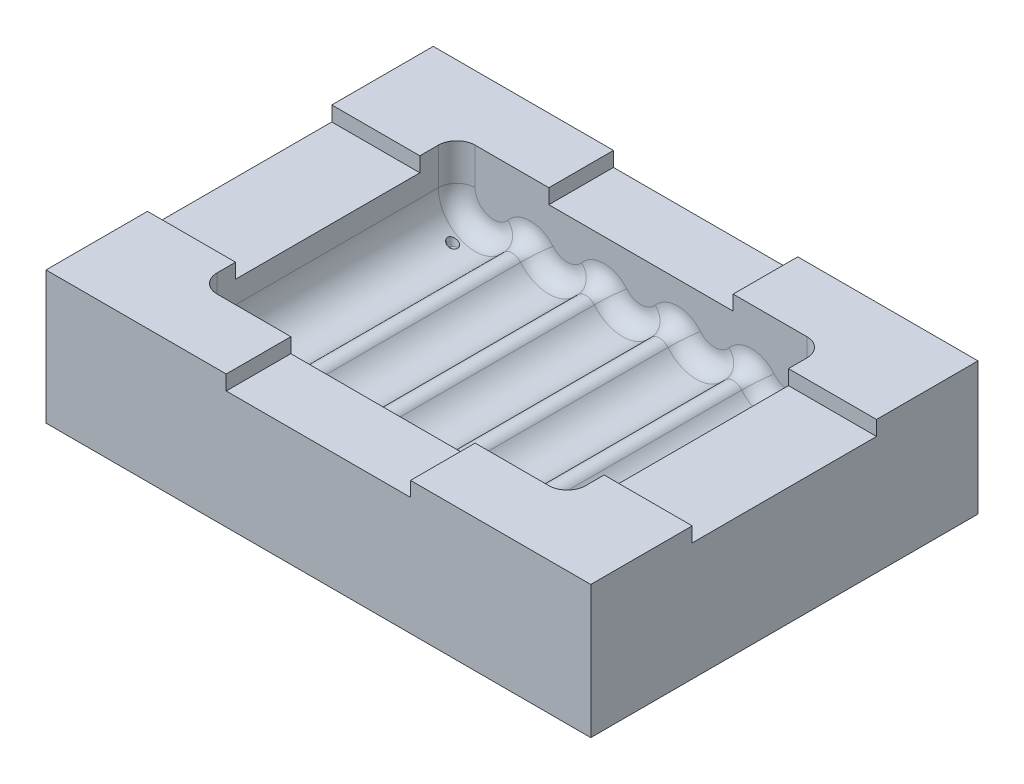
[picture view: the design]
ISO-10303-21;
HEADER;
FILE_DESCRIPTION(('STEP AP214'),'2;1');
FILE_NAME('part.step','',(''),(''),'','','');
FILE_SCHEMA(('AUTOMOTIVE_DESIGN { 1 0 10303 214 1 1 1 1 }'));
ENDSEC;
DATA;
#1=APPLICATION_CONTEXT('core data for automotive mechanical design processes');
#2=APPLICATION_PROTOCOL_DEFINITION('international standard','automotive_design',2000,#1);
#3=PRODUCT_CONTEXT('',#1,'mechanical');
#4=PRODUCT('Part','Part','',(#3));
#5=PRODUCT_RELATED_PRODUCT_CATEGORY('part','',(#4));
#6=PRODUCT_DEFINITION_FORMATION('','',#4);
#7=PRODUCT_DEFINITION_CONTEXT('part definition',#1,'design');
#8=PRODUCT_DEFINITION('design','',#6,#7);
#9=PRODUCT_DEFINITION_SHAPE('','',#8);
#10=(LENGTH_UNIT() NAMED_UNIT(*) SI_UNIT(.MILLI.,.METRE.));
#11=(NAMED_UNIT(*) PLANE_ANGLE_UNIT() SI_UNIT($,.RADIAN.));
#12=(NAMED_UNIT(*) SI_UNIT($,.STERADIAN.) SOLID_ANGLE_UNIT());
#13=UNCERTAINTY_MEASURE_WITH_UNIT(LENGTH_MEASURE(1.E-05),#10,'distance_accuracy_value','');
#14=(GEOMETRIC_REPRESENTATION_CONTEXT(3) GLOBAL_UNCERTAINTY_ASSIGNED_CONTEXT((#13)) GLOBAL_UNIT_ASSIGNED_CONTEXT((#10,
#11,#12)) REPRESENTATION_CONTEXT('',''));
#15=CARTESIAN_POINT('',(0.,0.,0.));
#16=DIRECTION('',(0.,0.,1.));
#17=DIRECTION('',(1.,0.,0.));
#18=AXIS2_PLACEMENT_3D('',#15,#16,#17);
#19=CARTESIAN_POINT('',(0.,-18.,0.));
#20=DIRECTION('',(0.,-1.,0.));
#21=DIRECTION('',(0.,0.,-1.));
#22=AXIS2_PLACEMENT_3D('',#19,#20,#21);
#23=PLANE('',#22);
#24=DIRECTION('',(0.,0.,1.));
#25=VECTOR('',#24,1.);
#26=CARTESIAN_POINT('',(-36.9482160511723,-18.,-26.2643843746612));
#27=LINE('',#26,#25);
#28=CARTESIAN_POINT('',(-36.9482160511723,-18.,-26.2643843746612));
#29=VERTEX_POINT('',#28);
#30=CARTESIAN_POINT('',(-36.9482160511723,-18.,26.2643843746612));
#31=VERTEX_POINT('',#30);
#32=EDGE_CURVE('E469',#29,#31,#27,.T.);
#33=ORIENTED_EDGE('',*,*,#32,.F.);
#34=DIRECTION('',(-1.,0.,0.));
#35=VECTOR('',#34,1.);
#36=CARTESIAN_POINT('',(36.9482160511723,-18.,-26.2643843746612));
#37=LINE('',#36,#35);
#38=CARTESIAN_POINT('',(36.9482160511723,-18.,-26.2643843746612));
#39=VERTEX_POINT('',#38);
#40=EDGE_CURVE('E484',#39,#29,#37,.T.);
#41=ORIENTED_EDGE('',*,*,#40,.F.);
#42=DIRECTION('',(0.,0.,-1.));
#43=VECTOR('',#42,1.);
#44=CARTESIAN_POINT('',(36.9482160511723,-18.,-26.2643843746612));
#45=LINE('',#44,#43);
#46=CARTESIAN_POINT('',(36.9482160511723,-18.,26.2643843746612));
#47=VERTEX_POINT('',#46);
#48=EDGE_CURVE('E471',#47,#39,#45,.T.);
#49=ORIENTED_EDGE('',*,*,#48,.F.);
#50=DIRECTION('',(1.,0.,0.));
#51=VECTOR('',#50,1.);
#52=CARTESIAN_POINT('',(36.9482160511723,-18.,26.2643843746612));
#53=LINE('',#52,#51);
#54=EDGE_CURVE('E456',#31,#47,#53,.T.);
#55=ORIENTED_EDGE('',*,*,#54,.F.);
#56=EDGE_LOOP('',(#33,#41,#49,#55));
#57=FACE_BOUND('',#56,.T.);
#58=ADVANCED_FACE('F158',(#57),#23,.T.);
#59=CARTESIAN_POINT('',(36.9482160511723,0.00150000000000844,-26.2643843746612));
#60=DIRECTION('',(0.,0.,1.));
#61=DIRECTION('',(1.,0.,0.));
#62=AXIS2_PLACEMENT_3D('',#59,#60,#61);
#63=PLANE('',#62);
#64=DIRECTION('',(0.,1.,0.));
#65=VECTOR('',#64,1.);
#66=CARTESIAN_POINT('',(12.5,0.00150000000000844,-26.2643843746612));
#67=LINE('',#66,#65);
#68=CARTESIAN_POINT('',(12.5,-2.,-26.2643843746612));
#69=VERTEX_POINT('',#68);
#70=CARTESIAN_POINT('',(12.5,0.,-26.2643843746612));
#71=VERTEX_POINT('',#70);
#72=EDGE_CURVE('E498',#69,#71,#67,.T.);
#73=ORIENTED_EDGE('',*,*,#72,.T.);
#74=DIRECTION('',(1.,0.,0.));
#75=VECTOR('',#74,1.);
#76=CARTESIAN_POINT('',(36.9482160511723,0.,-26.2643843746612));
#77=LINE('',#76,#75);
#78=CARTESIAN_POINT('',(36.9482160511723,0.,-26.2643843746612));
#79=VERTEX_POINT('',#78);
#80=EDGE_CURVE('E501',#71,#79,#77,.T.);
#81=ORIENTED_EDGE('',*,*,#80,.T.);
#82=DIRECTION('',(0.,-1.,0.));
#83=VECTOR('',#82,1.);
#84=CARTESIAN_POINT('',(36.9482160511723,0.00150000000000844,-26.2643843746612));
#85=LINE('',#84,#83);
#86=EDGE_CURVE('E487',#79,#39,#85,.T.);
#87=ORIENTED_EDGE('',*,*,#86,.T.);
#88=ORIENTED_EDGE('',*,*,#40,.T.);
#89=DIRECTION('',(0.,-1.,0.));
#90=VECTOR('',#89,1.);
#91=CARTESIAN_POINT('',(-36.9482160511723,0.00150000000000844,-26.2643843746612));
#92=LINE('',#91,#90);
#93=CARTESIAN_POINT('',(-36.9482160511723,0.,-26.2643843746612));
#94=VERTEX_POINT('',#93);
#95=EDGE_CURVE('E476',#94,#29,#92,.T.);
#96=ORIENTED_EDGE('',*,*,#95,.F.);
#97=DIRECTION('',(1.,0.,0.));
#98=VECTOR('',#97,1.);
#99=CARTESIAN_POINT('',(36.9482160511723,0.,-26.2643843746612));
#100=LINE('',#99,#98);
#101=CARTESIAN_POINT('',(-12.5,0.,-26.2643843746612));
#102=VERTEX_POINT('',#101);
#103=EDGE_CURVE('E463',#94,#102,#100,.T.);
#104=ORIENTED_EDGE('',*,*,#103,.T.);
#105=DIRECTION('',(0.,-1.,0.));
#106=VECTOR('',#105,1.);
#107=CARTESIAN_POINT('',(-12.5,0.00150000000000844,-26.2643843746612));
#108=LINE('',#107,#106);
#109=CARTESIAN_POINT('',(-12.5,-2.,-26.2643843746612));
#110=VERTEX_POINT('',#109);
#111=EDGE_CURVE('E492',#102,#110,#108,.T.);
#112=ORIENTED_EDGE('',*,*,#111,.T.);
#113=DIRECTION('',(1.,0.,0.));
#114=VECTOR('',#113,1.);
#115=CARTESIAN_POINT('',(36.9482160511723,-2.,-26.2643843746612));
#116=LINE('',#115,#114);
#117=EDGE_CURVE('E495',#110,#69,#116,.T.);
#118=ORIENTED_EDGE('',*,*,#117,.T.);
#119=EDGE_LOOP('',(#73,#81,#87,#88,#96,#104,#112,#118));
#120=FACE_BOUND('',#119,.T.);
#121=ADVANCED_FACE('F755',(#120),#63,.F.);
#122=CARTESIAN_POINT('',(36.9482160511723,0.00150000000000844,-26.2643843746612));
#123=DIRECTION('',(-1.,0.,0.));
#124=DIRECTION('',(0.,0.,1.));
#125=AXIS2_PLACEMENT_3D('',#122,#123,#124);
#126=PLANE('',#125);
#127=ORIENTED_EDGE('',*,*,#86,.F.);
#128=DIRECTION('',(0.,0.,1.));
#129=VECTOR('',#128,1.);
#130=CARTESIAN_POINT('',(36.9482160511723,0.,-26.2643843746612));
#131=LINE('',#130,#129);
#132=CARTESIAN_POINT('',(36.9482160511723,0.,-12.5));
#133=VERTEX_POINT('',#132);
#134=EDGE_CURVE('E504',#79,#133,#131,.T.);
#135=ORIENTED_EDGE('',*,*,#134,.T.);
#136=DIRECTION('',(0.,-1.,0.));
#137=VECTOR('',#136,1.);
#138=CARTESIAN_POINT('',(36.9482160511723,0.00150000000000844,-12.5));
#139=LINE('',#138,#137);
#140=CARTESIAN_POINT('',(36.9482160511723,-1.99999999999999,-12.5));
#141=VERTEX_POINT('',#140);
#142=EDGE_CURVE('E515',#133,#141,#139,.T.);
#143=ORIENTED_EDGE('',*,*,#142,.T.);
#144=DIRECTION('',(0.,0.,1.));
#145=VECTOR('',#144,1.);
#146=CARTESIAN_POINT('',(36.9482160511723,-1.99999999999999,-26.2643843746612));
#147=LINE('',#146,#145);
#148=CARTESIAN_POINT('',(36.9482160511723,-1.99999999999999,12.5));
#149=VERTEX_POINT('',#148);
#150=EDGE_CURVE('E512',#141,#149,#147,.T.);
#151=ORIENTED_EDGE('',*,*,#150,.T.);
#152=DIRECTION('',(0.,1.,0.));
#153=VECTOR('',#152,1.);
#154=CARTESIAN_POINT('',(36.9482160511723,0.00150000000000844,12.5));
#155=LINE('',#154,#153);
#156=CARTESIAN_POINT('',(36.9482160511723,0.,12.5));
#157=VERTEX_POINT('',#156);
#158=EDGE_CURVE('E509',#149,#157,#155,.T.);
#159=ORIENTED_EDGE('',*,*,#158,.T.);
#160=DIRECTION('',(0.,0.,1.));
#161=VECTOR('',#160,1.);
#162=CARTESIAN_POINT('',(36.9482160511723,0.,-26.2643843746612));
#163=LINE('',#162,#161);
#164=CARTESIAN_POINT('',(36.9482160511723,0.,26.2643843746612));
#165=VERTEX_POINT('',#164);
#166=EDGE_CURVE('E505',#157,#165,#163,.T.);
#167=ORIENTED_EDGE('',*,*,#166,.T.);
#168=DIRECTION('',(0.,-1.,0.));
#169=VECTOR('',#168,1.);
#170=CARTESIAN_POINT('',(36.9482160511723,0.00150000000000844,26.2643843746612));
#171=LINE('',#170,#169);
#172=EDGE_CURVE('E464',#165,#47,#171,.T.);
#173=ORIENTED_EDGE('',*,*,#172,.T.);
#174=ORIENTED_EDGE('',*,*,#48,.T.);
#175=EDGE_LOOP('',(#127,#135,#143,#151,#159,#167,#173,#174));
#176=FACE_BOUND('',#175,.T.);
#177=ADVANCED_FACE('F753',(#176),#126,.F.);
#178=CARTESIAN_POINT('',(36.9482160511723,0.00150000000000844,26.2643843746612));
#179=DIRECTION('',(0.,0.,-1.));
#180=DIRECTION('',(-1.,0.,0.));
#181=AXIS2_PLACEMENT_3D('',#178,#179,#180);
#182=PLANE('',#181);
#183=ORIENTED_EDGE('',*,*,#172,.F.);
#184=DIRECTION('',(-1.,0.,0.));
#185=VECTOR('',#184,1.);
#186=CARTESIAN_POINT('',(36.9482160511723,0.,26.2643843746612));
#187=LINE('',#186,#185);
#188=CARTESIAN_POINT('',(12.5,0.,26.2643843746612));
#189=VERTEX_POINT('',#188);
#190=EDGE_CURVE('E508',#165,#189,#187,.T.);
#191=ORIENTED_EDGE('',*,*,#190,.T.);
#192=DIRECTION('',(0.,-1.,0.));
#193=VECTOR('',#192,1.);
#194=CARTESIAN_POINT('',(12.5,0.00150000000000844,26.2643843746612));
#195=LINE('',#194,#193);
#196=CARTESIAN_POINT('',(12.5,-2.,26.2643843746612));
#197=VERTEX_POINT('',#196);
#198=EDGE_CURVE('E523',#189,#197,#195,.T.);
#199=ORIENTED_EDGE('',*,*,#198,.T.);
#200=DIRECTION('',(-1.,0.,0.));
#201=VECTOR('',#200,1.);
#202=CARTESIAN_POINT('',(36.9482160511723,-2.,26.2643843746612));
#203=LINE('',#202,#201);
#204=CARTESIAN_POINT('',(-12.5,-2.,26.2643843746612));
#205=VERTEX_POINT('',#204);
#206=EDGE_CURVE('E520',#197,#205,#203,.T.);
#207=ORIENTED_EDGE('',*,*,#206,.T.);
#208=DIRECTION('',(0.,1.,0.));
#209=VECTOR('',#208,1.);
#210=CARTESIAN_POINT('',(-12.5,0.00150000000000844,26.2643843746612));
#211=LINE('',#210,#209);
#212=CARTESIAN_POINT('',(-12.5,0.,26.2643843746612));
#213=VERTEX_POINT('',#212);
#214=EDGE_CURVE('E518',#205,#213,#211,.T.);
#215=ORIENTED_EDGE('',*,*,#214,.T.);
#216=DIRECTION('',(-1.,0.,0.));
#217=VECTOR('',#216,1.);
#218=CARTESIAN_POINT('',(36.9482160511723,0.,26.2643843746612));
#219=LINE('',#218,#217);
#220=CARTESIAN_POINT('',(-36.9482160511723,0.,26.2643843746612));
#221=VERTEX_POINT('',#220);
#222=EDGE_CURVE('E459',#213,#221,#219,.T.);
#223=ORIENTED_EDGE('',*,*,#222,.T.);
#224=DIRECTION('',(0.,-1.,0.));
#225=VECTOR('',#224,1.);
#226=CARTESIAN_POINT('',(-36.9482160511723,0.00150000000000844,26.2643843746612));
#227=LINE('',#226,#225);
#228=EDGE_CURVE('E452',#221,#31,#227,.T.);
#229=ORIENTED_EDGE('',*,*,#228,.T.);
#230=ORIENTED_EDGE('',*,*,#54,.T.);
#231=EDGE_LOOP('',(#183,#191,#199,#207,#215,#223,#229,#230));
#232=FACE_BOUND('',#231,.T.);
#233=ADVANCED_FACE('F455',(#232),#182,.F.);
#234=CARTESIAN_POINT('',(-36.9482160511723,0.00150000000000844,-26.2643843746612));
#235=DIRECTION('',(1.,0.,0.));
#236=DIRECTION('',(0.,0.,-1.));
#237=AXIS2_PLACEMENT_3D('',#234,#235,#236);
#238=PLANE('',#237);
#239=DIRECTION('',(0.,1.,0.));
#240=VECTOR('',#239,1.);
#241=CARTESIAN_POINT('',(-36.9482160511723,0.00150000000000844,-12.5));
#242=LINE('',#241,#240);
#243=CARTESIAN_POINT('',(-36.9482160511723,-1.99999999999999,-12.5));
#244=VERTEX_POINT('',#243);
#245=CARTESIAN_POINT('',(-36.9482160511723,0.,-12.5));
#246=VERTEX_POINT('',#245);
#247=EDGE_CURVE('E162',#244,#246,#242,.T.);
#248=ORIENTED_EDGE('',*,*,#247,.T.);
#249=DIRECTION('',(0.,0.,-1.));
#250=VECTOR('',#249,1.);
#251=CARTESIAN_POINT('',(-36.9482160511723,0.,-26.2643843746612));
#252=LINE('',#251,#250);
#253=EDGE_CURVE('E531',#246,#94,#252,.T.);
#254=ORIENTED_EDGE('',*,*,#253,.T.);
#255=ORIENTED_EDGE('',*,*,#95,.T.);
#256=ORIENTED_EDGE('',*,*,#32,.T.);
#257=ORIENTED_EDGE('',*,*,#228,.F.);
#258=DIRECTION('',(0.,0.,-1.));
#259=VECTOR('',#258,1.);
#260=CARTESIAN_POINT('',(-36.9482160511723,0.,-26.2643843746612));
#261=LINE('',#260,#259);
#262=CARTESIAN_POINT('',(-36.9482160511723,0.,12.5));
#263=VERTEX_POINT('',#262);
#264=EDGE_CURVE('E480',#221,#263,#261,.T.);
#265=ORIENTED_EDGE('',*,*,#264,.T.);
#266=DIRECTION('',(0.,-1.,0.));
#267=VECTOR('',#266,1.);
#268=CARTESIAN_POINT('',(-36.9482160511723,0.00150000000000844,12.5));
#269=LINE('',#268,#267);
#270=CARTESIAN_POINT('',(-36.9482160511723,-1.99999999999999,12.5));
#271=VERTEX_POINT('',#270);
#272=EDGE_CURVE('E527',#263,#271,#269,.T.);
#273=ORIENTED_EDGE('',*,*,#272,.T.);
#274=DIRECTION('',(0.,0.,-1.));
#275=VECTOR('',#274,1.);
#276=CARTESIAN_POINT('',(-36.9482160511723,-1.99999999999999,-26.2643843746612));
#277=LINE('',#276,#275);
#278=EDGE_CURVE('E529',#271,#244,#277,.T.);
#279=ORIENTED_EDGE('',*,*,#278,.T.);
#280=EDGE_LOOP('',(#248,#254,#255,#256,#257,#265,#273,#279));
#281=FACE_BOUND('',#280,.T.);
#282=ADVANCED_FACE('F160',(#281),#238,.F.);
#283=CARTESIAN_POINT('',(-25.,-1.99999999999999,-12.5));
#284=DIRECTION('',(0.,0.,-1.));
#285=DIRECTION('',(-1.,0.,0.));
#286=AXIS2_PLACEMENT_3D('',#283,#284,#285);
#287=PLANE('',#286);
#288=CARTESIAN_POINT('',(-25.,-1.99999999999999,-12.5));
#289=CARTESIAN_POINT('',(-45.,-1.99999999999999,-12.5));
#290=B_SPLINE_CURVE_WITH_KNOTS('',1,(#288,#289),.UNSPECIFIED.,.F.,.F.,(2,2),(0.,1.),.UNSPECIFIED.);
#291=CARTESIAN_POINT('',(-25.,-1.99999999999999,-12.5));
#292=VERTEX_POINT('',#291);
#293=EDGE_CURVE('E532',#292,#244,#290,.T.);
#294=ORIENTED_EDGE('',*,*,#293,.F.);
#295=DIRECTION('',(0.,1.,0.));
#296=VECTOR('',#295,1.);
#297=CARTESIAN_POINT('',(-25.,2.00000000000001,-12.5));
#298=LINE('',#297,#296);
#299=CARTESIAN_POINT('',(-25.,0.,-12.5));
#300=VERTEX_POINT('',#299);
#301=EDGE_CURVE('E559',#292,#300,#298,.T.);
#302=ORIENTED_EDGE('',*,*,#301,.T.);
#303=DIRECTION('',(-1.,0.,0.));
#304=VECTOR('',#303,1.);
#305=CARTESIAN_POINT('',(-25.,0.,-12.5));
#306=LINE('',#305,#304);
#307=EDGE_CURVE('E535',#300,#246,#306,.T.);
#308=ORIENTED_EDGE('',*,*,#307,.T.);
#309=ORIENTED_EDGE('',*,*,#247,.F.);
#310=EDGE_LOOP('',(#294,#302,#308,#309));
#311=FACE_BOUND('',#310,.T.);
#312=ADVANCED_FACE('F894',(#311),#287,.F.);
#313=CARTESIAN_POINT('',(-25.,-1.99999999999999,12.5));
#314=DIRECTION('',(0.,-1.,0.));
#315=DIRECTION('',(0.,0.,-1.));
#316=AXIS2_PLACEMENT_3D('',#313,#314,#315);
#317=PLANE('',#316);
#318=DIRECTION('',(-1.,0.,0.));
#319=VECTOR('',#318,1.);
#320=CARTESIAN_POINT('',(-25.,-1.99999999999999,12.5));
#321=LINE('',#320,#319);
#322=CARTESIAN_POINT('',(-25.,-1.99999999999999,12.5));
#323=VERTEX_POINT('',#322);
#324=EDGE_CURVE('E584',#323,#271,#321,.T.);
#325=ORIENTED_EDGE('',*,*,#324,.F.);
#326=DIRECTION('',(0.,0.,-1.));
#327=VECTOR('',#326,1.);
#328=CARTESIAN_POINT('',(-25.,-1.99999999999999,12.5));
#329=LINE('',#328,#327);
#330=EDGE_CURVE('E843',#323,#292,#329,.T.);
#331=ORIENTED_EDGE('',*,*,#330,.T.);
#332=ORIENTED_EDGE('',*,*,#293,.T.);
#333=ORIENTED_EDGE('',*,*,#278,.F.);
#334=EDGE_LOOP('',(#325,#331,#332,#333));
#335=FACE_BOUND('',#334,.T.);
#336=ADVANCED_FACE('F885',(#335),#317,.F.);
#337=CARTESIAN_POINT('',(-25.,0.,12.5));
#338=DIRECTION('',(0.,0.,1.));
#339=DIRECTION('',(-1.,0.,0.));
#340=AXIS2_PLACEMENT_3D('',#337,#338,#339);
#341=PLANE('',#340);
#342=CARTESIAN_POINT('',(-25.,0.,12.5));
#343=CARTESIAN_POINT('',(-45.,0.,12.5));
#344=B_SPLINE_CURVE_WITH_KNOTS('',1,(#342,#343),.UNSPECIFIED.,.F.,.F.,(2,2),(0.,1.),.UNSPECIFIED.);
#345=CARTESIAN_POINT('',(-25.,0.,12.5));
#346=VERTEX_POINT('',#345);
#347=EDGE_CURVE('E841',#346,#263,#344,.T.);
#348=ORIENTED_EDGE('',*,*,#347,.F.);
#349=DIRECTION('',(0.,-1.,0.));
#350=VECTOR('',#349,1.);
#351=CARTESIAN_POINT('',(-25.,2.00000000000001,12.5));
#352=LINE('',#351,#350);
#353=EDGE_CURVE('E655',#346,#323,#352,.T.);
#354=ORIENTED_EDGE('',*,*,#353,.T.);
#355=ORIENTED_EDGE('',*,*,#324,.T.);
#356=ORIENTED_EDGE('',*,*,#272,.F.);
#357=EDGE_LOOP('',(#348,#354,#355,#356));
#358=FACE_BOUND('',#357,.T.);
#359=ADVANCED_FACE('F876',(#358),#341,.F.);
#360=CARTESIAN_POINT('',(12.5,0.,17.5));
#361=DIRECTION('',(1.,0.,0.));
#362=DIRECTION('',(0.,0.,1.));
#363=AXIS2_PLACEMENT_3D('',#360,#361,#362);
#364=PLANE('',#363);
#365=DIRECTION('',(0.,0.,1.));
#366=VECTOR('',#365,1.);
#367=CARTESIAN_POINT('',(12.5,0.,17.5));
#368=LINE('',#367,#366);
#369=CARTESIAN_POINT('',(12.5,0.,17.5));
#370=VERTEX_POINT('',#369);
#371=EDGE_CURVE('E596',#370,#189,#368,.T.);
#372=ORIENTED_EDGE('',*,*,#371,.F.);
#373=DIRECTION('',(0.,1.,0.));
#374=VECTOR('',#373,1.);
#375=CARTESIAN_POINT('',(12.5,2.,17.5));
#376=LINE('',#375,#374);
#377=CARTESIAN_POINT('',(12.5,-2.,17.5));
#378=VERTEX_POINT('',#377);
#379=EDGE_CURVE('E595',#378,#370,#376,.T.);
#380=ORIENTED_EDGE('',*,*,#379,.F.);
#381=CARTESIAN_POINT('',(12.5,-2.,17.5));
#382=CARTESIAN_POINT('',(12.5,-2.,37.5));
#383=B_SPLINE_CURVE_WITH_KNOTS('',1,(#381,#382),.UNSPECIFIED.,.F.,.F.,(2,2),(0.,1.),.UNSPECIFIED.);
#384=EDGE_CURVE('E593',#197,#378,#383,.F.);
#385=ORIENTED_EDGE('',*,*,#384,.F.);
#386=ORIENTED_EDGE('',*,*,#198,.F.);
#387=EDGE_LOOP('',(#372,#380,#385,#386));
#388=FACE_BOUND('',#387,.T.);
#389=ADVANCED_FACE('F861',(#388),#364,.F.);
#390=CARTESIAN_POINT('',(-12.5,0.,17.5));
#391=DIRECTION('',(0.,-1.,0.));
#392=DIRECTION('',(0.,0.,-1.));
#393=AXIS2_PLACEMENT_3D('',#390,#391,#392);
#394=PLANE('',#393);
#395=ORIENTED_EDGE('',*,*,#222,.F.);
#396=DIRECTION('',(0.,0.,1.));
#397=VECTOR('',#396,1.);
#398=CARTESIAN_POINT('',(-12.5,0.,17.5));
#399=LINE('',#398,#397);
#400=CARTESIAN_POINT('',(-12.5,0.,17.5));
#401=VERTEX_POINT('',#400);
#402=EDGE_CURVE('E624',#401,#213,#399,.T.);
#403=ORIENTED_EDGE('',*,*,#402,.F.);
#404=DIRECTION('',(-1.,0.,0.));
#405=VECTOR('',#404,1.);
#406=CARTESIAN_POINT('',(-25.,0.,17.5));
#407=LINE('',#406,#405);
#408=CARTESIAN_POINT('',(-22.5,0.,17.5));
#409=VERTEX_POINT('',#408);
#410=EDGE_CURVE('E621',#401,#409,#407,.T.);
#411=ORIENTED_EDGE('',*,*,#410,.T.);
#412=CARTESIAN_POINT('',(-22.5,0.,15.));
#413=DIRECTION('',(0.,-1.,0.));
#414=DIRECTION('',(1.,0.,0.));
#415=AXIS2_PLACEMENT_3D('',#412,#413,#414);
#416=CIRCLE('',#415,2.5);
#417=CARTESIAN_POINT('',(-25.,0.,15.));
#418=VERTEX_POINT('',#417);
#419=EDGE_CURVE('E625',#418,#409,#416,.F.);
#420=ORIENTED_EDGE('',*,*,#419,.F.);
#421=DIRECTION('',(0.,0.,-1.));
#422=VECTOR('',#421,1.);
#423=CARTESIAN_POINT('',(-25.,0.,17.5));
#424=LINE('',#423,#422);
#425=EDGE_CURVE('E640',#418,#346,#424,.T.);
#426=ORIENTED_EDGE('',*,*,#425,.T.);
#427=ORIENTED_EDGE('',*,*,#347,.T.);
#428=ORIENTED_EDGE('',*,*,#264,.F.);
#429=EDGE_LOOP('',(#395,#403,#411,#420,#426,#427,#428));
#430=FACE_BOUND('',#429,.T.);
#431=ADVANCED_FACE('F982',(#430),#394,.F.);
#432=CARTESIAN_POINT('',(12.5,-2.,17.5));
#433=DIRECTION('',(0.,-1.,0.));
#434=DIRECTION('',(0.,0.,-1.));
#435=AXIS2_PLACEMENT_3D('',#432,#433,#434);
#436=PLANE('',#435);
#437=ORIENTED_EDGE('',*,*,#384,.T.);
#438=DIRECTION('',(1.,0.,0.));
#439=VECTOR('',#438,1.);
#440=CARTESIAN_POINT('',(-12.5,-2.,17.5));
#441=LINE('',#440,#439);
#442=CARTESIAN_POINT('',(-12.5,-2.,17.5));
#443=VERTEX_POINT('',#442);
#444=EDGE_CURVE('E633',#443,#378,#441,.T.);
#445=ORIENTED_EDGE('',*,*,#444,.F.);
#446=DIRECTION('',(0.,0.,1.));
#447=VECTOR('',#446,1.);
#448=CARTESIAN_POINT('',(-12.5,-2.,17.5));
#449=LINE('',#448,#447);
#450=EDGE_CURVE('E638',#443,#205,#449,.T.);
#451=ORIENTED_EDGE('',*,*,#450,.T.);
#452=ORIENTED_EDGE('',*,*,#206,.F.);
#453=EDGE_LOOP('',(#437,#445,#451,#452));
#454=FACE_BOUND('',#453,.T.);
#455=ADVANCED_FACE('F854',(#454),#436,.F.);
#456=CARTESIAN_POINT('',(-12.5,-2.,17.5));
#457=DIRECTION('',(-1.,0.,0.));
#458=DIRECTION('',(0.,0.,1.));
#459=AXIS2_PLACEMENT_3D('',#456,#457,#458);
#460=PLANE('',#459);
#461=ORIENTED_EDGE('',*,*,#450,.F.);
#462=DIRECTION('',(0.,-1.,0.));
#463=VECTOR('',#462,1.);
#464=CARTESIAN_POINT('',(-12.5,2.,17.5));
#465=LINE('',#464,#463);
#466=EDGE_CURVE('E631',#401,#443,#465,.T.);
#467=ORIENTED_EDGE('',*,*,#466,.F.);
#468=ORIENTED_EDGE('',*,*,#402,.T.);
#469=ORIENTED_EDGE('',*,*,#214,.F.);
#470=EDGE_LOOP('',(#461,#467,#468,#469));
#471=FACE_BOUND('',#470,.T.);
#472=ADVANCED_FACE('F987',(#471),#460,.F.);
#473=CARTESIAN_POINT('',(25.,0.,-12.5));
#474=DIRECTION('',(0.,0.,-1.));
#475=DIRECTION('',(1.,0.,0.));
#476=AXIS2_PLACEMENT_3D('',#473,#474,#475);
#477=PLANE('',#476);
#478=DIRECTION('',(1.,0.,0.));
#479=VECTOR('',#478,1.);
#480=CARTESIAN_POINT('',(25.,0.,-12.5));
#481=LINE('',#480,#479);
#482=CARTESIAN_POINT('',(25.,0.,-12.5));
#483=VERTEX_POINT('',#482);
#484=EDGE_CURVE('E592',#483,#133,#481,.T.);
#485=ORIENTED_EDGE('',*,*,#484,.F.);
#486=DIRECTION('',(0.,1.,0.));
#487=VECTOR('',#486,1.);
#488=CARTESIAN_POINT('',(25.,2.00000000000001,-12.5));
#489=LINE('',#488,#487);
#490=CARTESIAN_POINT('',(25.,-1.99999999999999,-12.5));
#491=VERTEX_POINT('',#490);
#492=EDGE_CURVE('E577',#491,#483,#489,.T.);
#493=ORIENTED_EDGE('',*,*,#492,.F.);
#494=CARTESIAN_POINT('',(25.,-1.99999999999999,-12.5));
#495=CARTESIAN_POINT('',(45.,-1.99999999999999,-12.5));
#496=B_SPLINE_CURVE_WITH_KNOTS('',1,(#494,#495),.UNSPECIFIED.,.F.,.F.,(2,2),(0.,1.),.UNSPECIFIED.);
#497=EDGE_CURVE('E590',#141,#491,#496,.F.);
#498=ORIENTED_EDGE('',*,*,#497,.F.);
#499=ORIENTED_EDGE('',*,*,#142,.F.);
#500=EDGE_LOOP('',(#485,#493,#498,#499));
#501=FACE_BOUND('',#500,.T.);
#502=ADVANCED_FACE('F816',(#501),#477,.F.);
#503=CARTESIAN_POINT('',(25.,-1.99999999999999,-12.5));
#504=DIRECTION('',(0.,-1.,0.));
#505=DIRECTION('',(0.,0.,-1.));
#506=AXIS2_PLACEMENT_3D('',#503,#504,#505);
#507=PLANE('',#506);
#508=ORIENTED_EDGE('',*,*,#497,.T.);
#509=DIRECTION('',(0.,0.,-1.));
#510=VECTOR('',#509,1.);
#511=CARTESIAN_POINT('',(25.,-1.99999999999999,12.5));
#512=LINE('',#511,#510);
#513=CARTESIAN_POINT('',(25.,-1.99999999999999,12.5));
#514=VERTEX_POINT('',#513);
#515=EDGE_CURVE('E576',#514,#491,#512,.T.);
#516=ORIENTED_EDGE('',*,*,#515,.F.);
#517=DIRECTION('',(1.,0.,0.));
#518=VECTOR('',#517,1.);
#519=CARTESIAN_POINT('',(25.,-1.99999999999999,12.5));
#520=LINE('',#519,#518);
#521=EDGE_CURVE('E570',#514,#149,#520,.T.);
#522=ORIENTED_EDGE('',*,*,#521,.T.);
#523=ORIENTED_EDGE('',*,*,#150,.F.);
#524=EDGE_LOOP('',(#508,#516,#522,#523));
#525=FACE_BOUND('',#524,.T.);
#526=ADVANCED_FACE('F818',(#525),#507,.F.);
#527=CARTESIAN_POINT('',(25.,-1.99999999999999,12.5));
#528=DIRECTION('',(0.,0.,1.));
#529=DIRECTION('',(1.,0.,0.));
#530=AXIS2_PLACEMENT_3D('',#527,#528,#529);
#531=PLANE('',#530);
#532=ORIENTED_EDGE('',*,*,#521,.F.);
#533=DIRECTION('',(0.,-1.,0.));
#534=VECTOR('',#533,1.);
#535=CARTESIAN_POINT('',(25.,2.00000000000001,12.5));
#536=LINE('',#535,#534);
#537=CARTESIAN_POINT('',(25.,0.,12.5));
#538=VERTEX_POINT('',#537);
#539=EDGE_CURVE('E612',#538,#514,#536,.T.);
#540=ORIENTED_EDGE('',*,*,#539,.F.);
#541=CARTESIAN_POINT('',(25.,0.,12.5));
#542=CARTESIAN_POINT('',(45.,0.,12.5));
#543=B_SPLINE_CURVE_WITH_KNOTS('',1,(#541,#542),.UNSPECIFIED.,.F.,.F.,(2,2),(0.,1.),.UNSPECIFIED.);
#544=EDGE_CURVE('E807',#157,#538,#543,.F.);
#545=ORIENTED_EDGE('',*,*,#544,.F.);
#546=ORIENTED_EDGE('',*,*,#158,.F.);
#547=EDGE_LOOP('',(#532,#540,#545,#546));
#548=FACE_BOUND('',#547,.T.);
#549=ADVANCED_FACE('F822',(#548),#531,.F.);
#550=CARTESIAN_POINT('',(25.,0.,12.5));
#551=DIRECTION('',(0.,-1.,0.));
#552=DIRECTION('',(0.,0.,-1.));
#553=AXIS2_PLACEMENT_3D('',#550,#551,#552);
#554=PLANE('',#553);
#555=ORIENTED_EDGE('',*,*,#166,.F.);
#556=ORIENTED_EDGE('',*,*,#544,.T.);
#557=DIRECTION('',(0.,0.,-1.));
#558=VECTOR('',#557,1.);
#559=CARTESIAN_POINT('',(25.,0.,17.5));
#560=LINE('',#559,#558);
#561=CARTESIAN_POINT('',(25.,0.,15.));
#562=VERTEX_POINT('',#561);
#563=EDGE_CURVE('E735',#562,#538,#560,.T.);
#564=ORIENTED_EDGE('',*,*,#563,.F.);
#565=CARTESIAN_POINT('',(22.5,0.,15.));
#566=DIRECTION('',(0.,-1.,0.));
#567=DIRECTION('',(1.,0.,0.));
#568=AXIS2_PLACEMENT_3D('',#565,#566,#567);
#569=CIRCLE('',#568,2.5);
#570=CARTESIAN_POINT('',(22.5,0.,17.5));
#571=VERTEX_POINT('',#570);
#572=EDGE_CURVE('E611',#571,#562,#569,.F.);
#573=ORIENTED_EDGE('',*,*,#572,.F.);
#574=EDGE_CURVE('E604',#571,#370,#407,.T.);
#575=ORIENTED_EDGE('',*,*,#574,.T.);
#576=ORIENTED_EDGE('',*,*,#371,.T.);
#577=ORIENTED_EDGE('',*,*,#190,.F.);
#578=EDGE_LOOP('',(#555,#556,#564,#573,#575,#576,#577));
#579=FACE_BOUND('',#578,.T.);
#580=ADVANCED_FACE('F862',(#579),#554,.F.);
#581=CARTESIAN_POINT('',(12.5,-2.,-17.5));
#582=DIRECTION('',(1.,0.,0.));
#583=DIRECTION('',(0.,0.,-1.));
#584=AXIS2_PLACEMENT_3D('',#581,#582,#583);
#585=PLANE('',#584);
#586=CARTESIAN_POINT('',(12.5,-2.,-17.5));
#587=CARTESIAN_POINT('',(12.5,-2.,-37.5));
#588=B_SPLINE_CURVE_WITH_KNOTS('',1,(#586,#587),.UNSPECIFIED.,.F.,.F.,(2,2),(0.,1.),.UNSPECIFIED.);
#589=CARTESIAN_POINT('',(12.5,-2.,-17.5));
#590=VERTEX_POINT('',#589);
#591=EDGE_CURVE('E545',#590,#69,#588,.T.);
#592=ORIENTED_EDGE('',*,*,#591,.F.);
#593=DIRECTION('',(0.,1.,0.));
#594=VECTOR('',#593,1.);
#595=CARTESIAN_POINT('',(12.5,2.,-17.5));
#596=LINE('',#595,#594);
#597=CARTESIAN_POINT('',(12.5,0.,-17.5));
#598=VERTEX_POINT('',#597);
#599=EDGE_CURVE('E544',#590,#598,#596,.T.);
#600=ORIENTED_EDGE('',*,*,#599,.T.);
#601=CARTESIAN_POINT('',(12.5,0.,-17.5));
#602=CARTESIAN_POINT('',(12.5,0.,-37.5));
#603=B_SPLINE_CURVE_WITH_KNOTS('',1,(#601,#602),.UNSPECIFIED.,.F.,.F.,(2,2),(0.,1.),.UNSPECIFIED.);
#604=EDGE_CURVE('E541',#71,#598,#603,.F.);
#605=ORIENTED_EDGE('',*,*,#604,.F.);
#606=ORIENTED_EDGE('',*,*,#72,.F.);
#607=EDGE_LOOP('',(#592,#600,#605,#606));
#608=FACE_BOUND('',#607,.T.);
#609=ADVANCED_FACE('F757',(#608),#585,.F.);
#610=CARTESIAN_POINT('',(-12.5,-2.,-17.5));
#611=DIRECTION('',(0.,-1.,0.));
#612=DIRECTION('',(0.,0.,-1.));
#613=AXIS2_PLACEMENT_3D('',#610,#611,#612);
#614=PLANE('',#613);
#615=DIRECTION('',(0.,0.,-1.));
#616=VECTOR('',#615,1.);
#617=CARTESIAN_POINT('',(-12.5,-2.,-17.5));
#618=LINE('',#617,#616);
#619=CARTESIAN_POINT('',(-12.5,-2.,-17.5));
#620=VERTEX_POINT('',#619);
#621=EDGE_CURVE('E717',#620,#110,#618,.T.);
#622=ORIENTED_EDGE('',*,*,#621,.F.);
#623=DIRECTION('',(1.,0.,0.));
#624=VECTOR('',#623,1.);
#625=CARTESIAN_POINT('',(-12.5,-2.,-17.5));
#626=LINE('',#625,#624);
#627=EDGE_CURVE('E713',#620,#590,#626,.T.);
#628=ORIENTED_EDGE('',*,*,#627,.T.);
#629=ORIENTED_EDGE('',*,*,#591,.T.);
#630=ORIENTED_EDGE('',*,*,#117,.F.);
#631=EDGE_LOOP('',(#622,#628,#629,#630));
#632=FACE_BOUND('',#631,.T.);
#633=ADVANCED_FACE('F759',(#632),#614,.F.);
#634=CARTESIAN_POINT('',(12.5,0.,-17.5));
#635=DIRECTION('',(0.,-1.,0.));
#636=DIRECTION('',(0.,0.,-1.));
#637=AXIS2_PLACEMENT_3D('',#634,#635,#636);
#638=PLANE('',#637);
#639=ORIENTED_EDGE('',*,*,#80,.F.);
#640=ORIENTED_EDGE('',*,*,#604,.T.);
#641=DIRECTION('',(-1.,0.,0.));
#642=VECTOR('',#641,1.);
#643=CARTESIAN_POINT('',(-25.,0.,-17.5));
#644=LINE('',#643,#642);
#645=CARTESIAN_POINT('',(22.5,0.,-17.5));
#646=VERTEX_POINT('',#645);
#647=EDGE_CURVE('E565',#646,#598,#644,.T.);
#648=ORIENTED_EDGE('',*,*,#647,.F.);
#649=CARTESIAN_POINT('',(22.5,0.,-15.));
#650=DIRECTION('',(0.,-1.,0.));
#651=DIRECTION('',(1.,0.,0.));
#652=AXIS2_PLACEMENT_3D('',#649,#650,#651);
#653=CIRCLE('',#652,2.5);
#654=CARTESIAN_POINT('',(25.,0.,-15.));
#655=VERTEX_POINT('',#654);
#656=EDGE_CURVE('E703',#655,#646,#653,.F.);
#657=ORIENTED_EDGE('',*,*,#656,.F.);
#658=EDGE_CURVE('E716',#483,#655,#560,.T.);
#659=ORIENTED_EDGE('',*,*,#658,.F.);
#660=ORIENTED_EDGE('',*,*,#484,.T.);
#661=ORIENTED_EDGE('',*,*,#134,.F.);
#662=EDGE_LOOP('',(#639,#640,#648,#657,#659,#660,#661));
#663=FACE_BOUND('',#662,.T.);
#664=ADVANCED_FACE('F747',(#663),#638,.F.);
#665=CARTESIAN_POINT('',(-12.5,0.,-17.5));
#666=DIRECTION('',(-1.,0.,0.));
#667=DIRECTION('',(0.,0.,-1.));
#668=AXIS2_PLACEMENT_3D('',#665,#666,#667);
#669=PLANE('',#668);
#670=CARTESIAN_POINT('',(-12.5,0.,-17.5));
#671=CARTESIAN_POINT('',(-12.5,0.,-37.5));
#672=B_SPLINE_CURVE_WITH_KNOTS('',1,(#670,#671),.UNSPECIFIED.,.F.,.F.,(2,2),(0.,1.),.UNSPECIFIED.);
#673=CARTESIAN_POINT('',(-12.5,0.,-17.5));
#674=VERTEX_POINT('',#673);
#675=EDGE_CURVE('E562',#674,#102,#672,.T.);
#676=ORIENTED_EDGE('',*,*,#675,.F.);
#677=DIRECTION('',(0.,-1.,0.));
#678=VECTOR('',#677,1.);
#679=CARTESIAN_POINT('',(-12.5,2.,-17.5));
#680=LINE('',#679,#678);
#681=EDGE_CURVE('E564',#674,#620,#680,.T.);
#682=ORIENTED_EDGE('',*,*,#681,.T.);
#683=ORIENTED_EDGE('',*,*,#621,.T.);
#684=ORIENTED_EDGE('',*,*,#111,.F.);
#685=EDGE_LOOP('',(#676,#682,#683,#684));
#686=FACE_BOUND('',#685,.T.);
#687=ADVANCED_FACE('F761',(#686),#669,.F.);
#688=CARTESIAN_POINT('',(-25.,0.,-12.5));
#689=DIRECTION('',(0.,-1.,0.));
#690=DIRECTION('',(0.,0.,-1.));
#691=AXIS2_PLACEMENT_3D('',#688,#689,#690);
#692=PLANE('',#691);
#693=ORIENTED_EDGE('',*,*,#307,.F.);
#694=CARTESIAN_POINT('',(-25.,0.,-15.));
#695=VERTEX_POINT('',#694);
#696=EDGE_CURVE('E666',#300,#695,#424,.T.);
#697=ORIENTED_EDGE('',*,*,#696,.T.);
#698=CARTESIAN_POINT('',(-22.5,0.,-15.));
#699=DIRECTION('',(0.,-1.,0.));
#700=DIRECTION('',(1.,0.,0.));
#701=AXIS2_PLACEMENT_3D('',#698,#699,#700);
#702=CIRCLE('',#701,2.5);
#703=CARTESIAN_POINT('',(-22.5,0.,-17.5));
#704=VERTEX_POINT('',#703);
#705=EDGE_CURVE('E670',#704,#695,#702,.F.);
#706=ORIENTED_EDGE('',*,*,#705,.F.);
#707=EDGE_CURVE('E689',#674,#704,#644,.T.);
#708=ORIENTED_EDGE('',*,*,#707,.F.);
#709=ORIENTED_EDGE('',*,*,#675,.T.);
#710=ORIENTED_EDGE('',*,*,#103,.F.);
#711=ORIENTED_EDGE('',*,*,#253,.F.);
#712=EDGE_LOOP('',(#693,#697,#706,#708,#709,#710,#711));
#713=FACE_BOUND('',#712,.T.);
#714=ADVANCED_FACE('F766',(#713),#692,.F.);
#715=CARTESIAN_POINT('',(-22.,-10.5,-14.));
#716=DIRECTION('',(0.,1.,0.));
#717=DIRECTION('',(0.,0.,1.));
#718=AXIS2_PLACEMENT_3D('',#715,#716,#717);
#719=PLANE('',#718);
#720=CARTESIAN_POINT('',(-22.,-10.5,-14.));
#721=DIRECTION('',(0.,1.,0.));
#722=DIRECTION('',(0.,0.,1.));
#723=AXIS2_PLACEMENT_3D('',#720,#721,#722);
#724=CIRCLE('',#723,0.290225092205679);
#725=CARTESIAN_POINT('',(-22.,-10.5,-13.7097749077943));
#726=VERTEX_POINT('',#725);
#727=EDGE_CURVE('E669',#726,#726,#724,.F.);
#728=ORIENTED_EDGE('',*,*,#727,.F.);
#729=EDGE_LOOP('',(#728));
#730=FACE_BOUND('',#729,.T.);
#731=ADVANCED_FACE('F965',(#730),#719,.T.);
#732=CARTESIAN_POINT('',(-22.,-10.25,-14.));
#733=DIRECTION('',(0.,1.,0.));
#734=DIRECTION('',(0.,0.,1.));
#735=AXIS2_PLACEMENT_3D('',#732,#733,#734);
#736=TOROIDAL_SURFACE('',#735,0.290225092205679,0.25);
#737=ORIENTED_EDGE('',*,*,#727,.T.);
#738=EDGE_LOOP('',(#737));
#739=FACE_BOUND('',#738,.T.);
#740=CARTESIAN_POINT('',(-22.,-10.2934120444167,-14.));
#741=DIRECTION('',(0.,-1.,0.));
#742=DIRECTION('',(0.,0.,-1.));
#743=AXIS2_PLACEMENT_3D('',#740,#741,#742);
#744=CIRCLE('',#743,0.536427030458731);
#745=CARTESIAN_POINT('',(-22.,-10.2934120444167,-14.5364270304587));
#746=VERTEX_POINT('',#745);
#747=EDGE_CURVE('E1661',#746,#746,#744,.F.);
#748=ORIENTED_EDGE('',*,*,#747,.T.);
#749=EDGE_LOOP('',(#748));
#750=FACE_BOUND('',#749,.T.);
#751=ADVANCED_FACE('F961',(#739,#750),#736,.F.);
#752=CARTESIAN_POINT('',(-22.,-10.5,-14.));
#753=DIRECTION('',(0.,1.,0.));
#754=DIRECTION('',(0.,0.,1.));
#755=AXIS2_PLACEMENT_3D('',#752,#753,#754);
#756=CONICAL_SURFACE('',#755,0.499999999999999,0.174532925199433);
#757=ORIENTED_EDGE('',*,*,#747,.F.);
#758=EDGE_LOOP('',(#757));
#759=FACE_BOUND('',#758,.T.);
#760=CARTESIAN_POINT('',(-22.522981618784,-9.31677700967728,-14.4781762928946));
#761=CARTESIAN_POINT('',(-22.4885081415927,-9.33692418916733,-14.5106134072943));
#762=CARTESIAN_POINT('',(-22.4509534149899,-9.35831249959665,-14.539102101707));
#763=CARTESIAN_POINT('',(-22.3712514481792,-9.40218636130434,-14.5876995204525));
#764=CARTESIAN_POINT('',(-22.3290921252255,-9.42467470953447,-14.6077854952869));
#765=CARTESIAN_POINT('',(-22.2462877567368,-9.46722756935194,-14.6374307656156));
#766=CARTESIAN_POINT('',(-22.2059625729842,-9.48729421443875,-14.6478857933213));
#767=CARTESIAN_POINT('',(-22.1238118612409,-9.52675334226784,-14.6613990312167));
#768=CARTESIAN_POINT('',(-22.0819879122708,-9.54614649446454,-14.6644648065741));
#769=CARTESIAN_POINT('',(-21.9968118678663,-9.58420912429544,-14.6628673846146));
#770=CARTESIAN_POINT('',(-21.9534485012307,-9.60284618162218,-14.6579989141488));
#771=CARTESIAN_POINT('',(-21.8677136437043,-9.63829659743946,-14.6398716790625));
#772=CARTESIAN_POINT('',(-21.8253420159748,-9.65511020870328,-14.6266140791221));
#773=CARTESIAN_POINT('',(-21.7462442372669,-9.68532773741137,-14.5929566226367));
#774=CARTESIAN_POINT('',(-21.7093312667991,-9.69888999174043,-14.5731397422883));
#775=CARTESIAN_POINT('',(-21.6393202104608,-9.72377063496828,-14.5265670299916));
#776=CARTESIAN_POINT('',(-21.6062195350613,-9.73509055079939,-14.4998159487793));
#777=CARTESIAN_POINT('',(-21.5481851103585,-9.75436356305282,-14.4428537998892));
#778=CARTESIAN_POINT('',(-21.5227777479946,-9.7625321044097,-14.4131974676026));
#779=CARTESIAN_POINT('',(-21.4773920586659,-9.77680650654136,-14.3495486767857));
#780=CARTESIAN_POINT('',(-21.4574113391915,-9.78291327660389,-14.315558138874));
#781=CARTESIAN_POINT('',(-21.4249064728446,-9.7926935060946,-14.2467517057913));
#782=CARTESIAN_POINT('',(-21.4119652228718,-9.79650502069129,-14.2121519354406));
#783=CARTESIAN_POINT('',(-21.3920572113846,-9.80232085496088,-14.1411302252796));
#784=CARTESIAN_POINT('',(-21.3850890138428,-9.80432560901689,-14.104708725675));
#785=CARTESIAN_POINT('',(-21.3775411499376,-9.8064950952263,-14.0324683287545));
#786=CARTESIAN_POINT('',(-21.3767436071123,-9.80672258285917,-13.9966738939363));
#787=CARTESIAN_POINT('',(-21.380992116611,-9.80550367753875,-13.9254645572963));
#788=CARTESIAN_POINT('',(-21.3860376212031,-9.80405744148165,-13.8900496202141));
#789=CARTESIAN_POINT('',(-21.4017142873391,-9.79950644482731,-13.820913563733));
#790=CARTESIAN_POINT('',(-21.4122972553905,-9.79641599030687,-13.7871805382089));
#791=CARTESIAN_POINT('',(-21.4386333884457,-9.78858241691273,-13.722006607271));
#792=CARTESIAN_POINT('',(-21.4543866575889,-9.7838392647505,-13.6905657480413));
#793=CARTESIAN_POINT('',(-21.490774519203,-9.77262585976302,-13.6303383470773));
#794=CARTESIAN_POINT('',(-21.511478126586,-9.76613100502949,-13.6015981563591));
#795=CARTESIAN_POINT('',(-21.5569131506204,-9.7514829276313,-13.5479922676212));
#796=CARTESIAN_POINT('',(-21.5816450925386,-9.74332948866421,-13.523127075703));
#797=CARTESIAN_POINT('',(-21.6353767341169,-9.72507965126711,-13.4768721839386));
#798=CARTESIAN_POINT('',(-21.6645069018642,-9.71491895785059,-13.4556596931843));
#799=CARTESIAN_POINT('',(-21.7253087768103,-9.69301118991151,-13.4183157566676));
#800=CARTESIAN_POINT('',(-21.7569811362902,-9.68126370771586,-13.4021856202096));
#801=CARTESIAN_POINT('',(-21.8241236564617,-9.65552875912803,-13.3742640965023));
#802=CARTESIAN_POINT('',(-21.8597062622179,-9.64144421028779,-13.3628332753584));
#803=CARTESIAN_POINT('',(-21.9317171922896,-9.61193939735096,-13.3459285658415));
#804=CARTESIAN_POINT('',(-21.9681458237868,-9.59651864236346,-13.3404568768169));
#805=CARTESIAN_POINT('',(-22.0441237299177,-9.56326872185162,-13.3351170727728));
#806=CARTESIAN_POINT('',(-22.0836694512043,-9.54534668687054,-13.3357764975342));
#807=CARTESIAN_POINT('',(-22.1617322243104,-9.50874435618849,-13.34371629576));
#808=CARTESIAN_POINT('',(-22.2002488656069,-9.49006376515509,-13.3509992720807));
#809=CARTESIAN_POINT('',(-22.2783432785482,-9.45097772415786,-13.3727311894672));
#810=CARTESIAN_POINT('',(-22.3177679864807,-9.43055174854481,-13.3876965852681));
#811=CARTESIAN_POINT('',(-22.3934424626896,-9.39013394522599,-13.4247056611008));
#812=CARTESIAN_POINT('',(-22.4296897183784,-9.37014247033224,-13.4467548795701));
#813=CARTESIAN_POINT('',(-22.4983303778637,-9.33127225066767,-13.4979468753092));
#814=CARTESIAN_POINT('',(-22.5306722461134,-9.31240976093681,-13.5271716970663));
#815=CARTESIAN_POINT('',(-22.5896428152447,-9.27725691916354,-13.592181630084));
#816=CARTESIAN_POINT('',(-22.6162828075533,-9.26096150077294,-13.6279535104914));
#817=CARTESIAN_POINT('',(-22.655740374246,-9.23643976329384,-13.6942595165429));
#818=CARTESIAN_POINT('',(-22.6703336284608,-9.22723723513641,-13.7233822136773));
#819=CARTESIAN_POINT('',(-22.6951860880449,-9.21143553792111,-13.7840847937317));
#820=CARTESIAN_POINT('',(-22.705449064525,-9.20483410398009,-13.8156625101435));
#821=CARTESIAN_POINT('',(-22.7211211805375,-9.19470965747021,-13.8806783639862));
#822=CARTESIAN_POINT('',(-22.7265036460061,-9.1912035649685,-13.9141256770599));
#823=CARTESIAN_POINT('',(-22.7319540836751,-9.18765311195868,-13.9816323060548));
#824=CARTESIAN_POINT('',(-22.7320239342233,-9.1876075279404,-14.0156914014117));
#825=CARTESIAN_POINT('',(-22.7270869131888,-9.19082366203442,-14.080169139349));
#826=CARTESIAN_POINT('',(-22.7225364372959,-9.19378805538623,-14.1106395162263));
#827=CARTESIAN_POINT('',(-22.709296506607,-9.2023533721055,-14.1702809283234));
#828=CARTESIAN_POINT('',(-22.7006057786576,-9.20795510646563,-14.1994515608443));
#829=CARTESIAN_POINT('',(-22.6792036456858,-9.22161490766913,-14.2566428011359));
#830=CARTESIAN_POINT('',(-22.6663848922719,-9.22973831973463,-14.2846070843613));
#831=CARTESIAN_POINT('',(-22.6373390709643,-9.24790947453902,-14.3379936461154));
#832=CARTESIAN_POINT('',(-22.6211134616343,-9.25795639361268,-14.3634170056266));
#833=CARTESIAN_POINT('',(-22.591302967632,-9.27613740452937,-14.4039163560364));
#834=CARTESIAN_POINT('',(-22.5784817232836,-9.28388558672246,-14.4197399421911));
#835=CARTESIAN_POINT('',(-22.5516183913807,-9.29994064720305,-14.4500038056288));
#836=CARTESIAN_POINT('',(-22.5375761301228,-9.30824760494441,-14.4644438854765));
#837=CARTESIAN_POINT('',(-22.522981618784,-9.31677700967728,-14.4781762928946));
#838=B_SPLINE_CURVE_WITH_KNOTS('',3,(#760,#761,#762,#763,#764,#765,#766,#767,#768,#769,#770,
#771,#772,#773,#774,#775,#776,#777,#778,#779,#780,#781,#782,#783,#784,#785,#786,#787,#788,#789,
#790,#791,#792,#793,#794,#795,#796,#797,#798,#799,#800,#801,#802,#803,#804,#805,#806,#807,#808,
#809,#810,#811,#812,#813,#814,#815,#816,#817,#818,#819,#820,#821,#822,#823,#824,#825,#826,#827,
#828,#829,#830,#831,#832,#833,#834,#835,#836,#837),.UNSPECIFIED.,.T.,.F.,(4,2,2,2,2,2,2,2,2,2,2,
2,2,2,2,2,2,2,2,2,2,2,2,2,2,2,2,2,2,2,2,2,2,2,2,2,2,2,4),(0.,0.154232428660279,
0.308879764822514,0.446996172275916,0.584971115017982,0.726572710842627,0.868154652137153,
0.999542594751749,1.13084075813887,1.24990351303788,1.36891368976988,1.47976959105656,
1.59059883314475,1.69749617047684,1.80438348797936,1.9103556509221,2.01632994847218,
2.12387799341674,2.23144007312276,2.34327320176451,2.45513511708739,2.57444805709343,
2.69380501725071,2.82352078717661,2.95328755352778,3.09321529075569,3.23325269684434,
3.37497261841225,3.51640924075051,3.61754933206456,3.71860116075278,3.82020200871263,
3.92176693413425,4.01418988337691,4.10664127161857,4.20172275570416,4.29676361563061,
4.36204934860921,4.42734438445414),.UNSPECIFIED.);
#839=CARTESIAN_POINT('',(-22.522981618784,-9.31677700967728,-14.4781762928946));
#840=VERTEX_POINT('',#839);
#841=EDGE_CURVE('E934',#840,#840,#838,.T.);
#842=ORIENTED_EDGE('',*,*,#841,.F.);
#843=EDGE_LOOP('',(#842));
#844=FACE_BOUND('',#843,.T.);
#845=ADVANCED_FACE('F956',(#759,#844),#756,.F.);
#846=CARTESIAN_POINT('',(-22.,-10.5,14.));
#847=DIRECTION('',(0.,1.,0.));
#848=DIRECTION('',(0.,0.,1.));
#849=AXIS2_PLACEMENT_3D('',#846,#847,#848);
#850=PLANE('',#849);
#851=CARTESIAN_POINT('',(-22.,-10.5,14.));
#852=DIRECTION('',(0.,1.,0.));
#853=DIRECTION('',(0.,0.,1.));
#854=AXIS2_PLACEMENT_3D('',#851,#852,#853);
#855=CIRCLE('',#854,0.290225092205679);
#856=CARTESIAN_POINT('',(-22.,-10.5,14.2902250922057));
#857=VERTEX_POINT('',#856);
#858=EDGE_CURVE('E1659',#857,#857,#855,.F.);
#859=ORIENTED_EDGE('',*,*,#858,.F.);
#860=EDGE_LOOP('',(#859));
#861=FACE_BOUND('',#860,.T.);
#862=ADVANCED_FACE('F953',(#861),#850,.T.);
#863=CARTESIAN_POINT('',(-22.,-10.25,14.));
#864=DIRECTION('',(0.,1.,0.));
#865=DIRECTION('',(0.,0.,1.));
#866=AXIS2_PLACEMENT_3D('',#863,#864,#865);
#867=TOROIDAL_SURFACE('',#866,0.290225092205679,0.25);
#868=ORIENTED_EDGE('',*,*,#858,.T.);
#869=EDGE_LOOP('',(#868));
#870=FACE_BOUND('',#869,.T.);
#871=CARTESIAN_POINT('',(-22.,-10.2934120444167,14.));
#872=DIRECTION('',(0.,-1.,0.));
#873=DIRECTION('',(0.,0.,-1.));
#874=AXIS2_PLACEMENT_3D('',#871,#872,#873);
#875=CIRCLE('',#874,0.536427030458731);
#876=CARTESIAN_POINT('',(-22.,-10.2934120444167,13.4635729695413));
#877=VERTEX_POINT('',#876);
#878=EDGE_CURVE('E933',#877,#877,#875,.F.);
#879=ORIENTED_EDGE('',*,*,#878,.T.);
#880=EDGE_LOOP('',(#879));
#881=FACE_BOUND('',#880,.T.);
#882=ADVANCED_FACE('F948',(#870,#881),#867,.F.);
#883=CARTESIAN_POINT('',(-22.,-10.5,14.));
#884=DIRECTION('',(0.,1.,0.));
#885=DIRECTION('',(0.,0.,1.));
#886=AXIS2_PLACEMENT_3D('',#883,#884,#885);
#887=CONICAL_SURFACE('',#886,0.499999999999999,0.174532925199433);
#888=ORIENTED_EDGE('',*,*,#878,.F.);
#889=EDGE_LOOP('',(#888));
#890=FACE_BOUND('',#889,.T.);
#891=CARTESIAN_POINT('',(-22.5245249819,-9.31587460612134,13.5232805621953));
#892=CARTESIAN_POINT('',(-22.4901331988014,-9.33599054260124,13.4907156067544));
#893=CARTESIAN_POINT('',(-22.4526455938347,-9.35735989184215,13.4620971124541));
#894=CARTESIAN_POINT('',(-22.3730543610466,-9.40121419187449,13.4132388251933));
#895=CARTESIAN_POINT('',(-22.3309385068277,-9.42370200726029,13.3930219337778));
#896=CARTESIAN_POINT('',(-22.2482383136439,-9.46624553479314,13.3631429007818));
#897=CARTESIAN_POINT('',(-22.2079786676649,-9.48630198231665,13.3525775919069));
#898=CARTESIAN_POINT('',(-22.125944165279,-9.52575177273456,13.3388266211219));
#899=CARTESIAN_POINT('',(-22.0841709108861,-9.54514577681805,13.3356333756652));
#900=CARTESIAN_POINT('',(-21.9990285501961,-9.583243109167,13.3369554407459));
#901=CARTESIAN_POINT('',(-21.9556470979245,-9.60191290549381,13.3416845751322));
#902=CARTESIAN_POINT('',(-21.8698501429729,-9.63743614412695,13.3595357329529));
#903=CARTESIAN_POINT('',(-21.827434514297,-9.65428982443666,13.3726566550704));
#904=CARTESIAN_POINT('',(-21.7482056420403,-9.68459698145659,13.4060666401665));
#905=CARTESIAN_POINT('',(-21.7112086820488,-9.69820744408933,13.4257758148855));
#906=CARTESIAN_POINT('',(-21.6410101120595,-9.72318465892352,13.472152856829));
#907=CARTESIAN_POINT('',(-21.6078059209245,-9.73455294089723,13.4988159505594));
#908=CARTESIAN_POINT('',(-21.5495619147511,-9.75391566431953,13.5556318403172));
#909=CARTESIAN_POINT('',(-21.5240494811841,-9.76212587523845,13.5852272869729));
#910=CARTESIAN_POINT('',(-21.4784451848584,-9.77648124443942,13.6487768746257));
#911=CARTESIAN_POINT('',(-21.4583509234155,-9.78262731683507,13.6827290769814));
#912=CARTESIAN_POINT('',(-21.4256288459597,-9.79247905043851,13.7514745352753));
#913=CARTESIAN_POINT('',(-21.412582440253,-9.79632352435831,13.7860492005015));
#914=CARTESIAN_POINT('',(-21.3924626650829,-9.80220354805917,13.8570406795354));
#915=CARTESIAN_POINT('',(-21.3853878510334,-9.80423953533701,13.8934570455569));
#916=CARTESIAN_POINT('',(-21.3776345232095,-9.80646841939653,13.9656971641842));
#917=CARTESIAN_POINT('',(-21.3767364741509,-9.80672457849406,14.0014955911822));
#918=CARTESIAN_POINT('',(-21.3807874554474,-9.80556244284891,14.0727303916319));
#919=CARTESIAN_POINT('',(-21.3857359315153,-9.80414430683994,14.108166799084));
#920=CARTESIAN_POINT('',(-21.4012247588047,-9.79964922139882,14.1773545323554));
#921=CARTESIAN_POINT('',(-21.4117157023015,-9.79658692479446,14.2111179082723));
#922=CARTESIAN_POINT('',(-21.437875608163,-9.78880974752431,14.2763674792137));
#923=CARTESIAN_POINT('',(-21.4535446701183,-9.78409483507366,14.3078536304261));
#924=CARTESIAN_POINT('',(-21.4897698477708,-9.77293920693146,14.3681791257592));
#925=CARTESIAN_POINT('',(-21.5103941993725,-9.7664742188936,14.3969729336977));
#926=CARTESIAN_POINT('',(-21.555682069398,-9.75188574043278,14.4506979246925));
#927=CARTESIAN_POINT('',(-21.5803461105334,-9.74376203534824,14.4756286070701));
#928=CARTESIAN_POINT('',(-21.633946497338,-9.72557395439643,14.5220211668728));
#929=CARTESIAN_POINT('',(-21.6630130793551,-9.71544561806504,14.5433072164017));
#930=CARTESIAN_POINT('',(-21.7237014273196,-9.69360135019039,14.5808069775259));
#931=CARTESIAN_POINT('',(-21.7553238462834,-9.68188501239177,14.5970193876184));
#932=CARTESIAN_POINT('',(-21.8223703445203,-9.65621486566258,14.6251140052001));
#933=CARTESIAN_POINT('',(-21.8579074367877,-9.64216415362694,14.6366372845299));
#934=CARTESIAN_POINT('',(-21.9298424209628,-9.61272379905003,14.653733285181));
#935=CARTESIAN_POINT('',(-21.9662406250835,-9.59733366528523,14.659303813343));
#936=CARTESIAN_POINT('',(-22.0421669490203,-9.56414439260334,14.6648542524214));
#937=CARTESIAN_POINT('',(-22.0816928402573,-9.54625207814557,14.6643076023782));
#938=CARTESIAN_POINT('',(-22.1597328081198,-9.50970223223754,14.6565983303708));
#939=CARTESIAN_POINT('',(-22.1982464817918,-9.49104440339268,14.6494331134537));
#940=CARTESIAN_POINT('',(-22.2763629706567,-9.45199092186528,14.6279478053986));
#941=CARTESIAN_POINT('',(-22.3158135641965,-9.43157391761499,14.6131097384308));
#942=CARTESIAN_POINT('',(-22.3915598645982,-9.39116009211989,14.5763572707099));
#943=CARTESIAN_POINT('',(-22.4278530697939,-9.37116361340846,14.5544373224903));
#944=CARTESIAN_POINT('',(-22.4966399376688,-9.33224772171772,14.5034847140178));
#945=CARTESIAN_POINT('',(-22.5290786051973,-9.31334551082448,14.4743640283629));
#946=CARTESIAN_POINT('',(-22.5882628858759,-9.2780930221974,14.4095489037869));
#947=CARTESIAN_POINT('',(-22.6150196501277,-9.26173776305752,14.3738676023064));
#948=CARTESIAN_POINT('',(-22.6547147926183,-9.23708308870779,14.307667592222));
#949=CARTESIAN_POINT('',(-22.6694193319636,-9.22781511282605,14.2785624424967));
#950=CARTESIAN_POINT('',(-22.6944946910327,-9.21187838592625,14.217873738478));
#951=CARTESIAN_POINT('',(-22.7048692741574,-9.20520737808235,14.1862923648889));
#952=CARTESIAN_POINT('',(-22.7207607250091,-9.19494375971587,14.1212433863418));
#953=CARTESIAN_POINT('',(-22.7262506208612,-9.19136824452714,14.0877663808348));
#954=CARTESIAN_POINT('',(-22.7319027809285,-9.18768668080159,14.0201770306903));
#955=CARTESIAN_POINT('',(-22.732066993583,-9.1875793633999,13.9860649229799));
#956=CARTESIAN_POINT('',(-22.7272938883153,-9.1906889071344,13.9215025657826));
#957=CARTESIAN_POINT('',(-22.722819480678,-9.19360413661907,13.8910015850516));
#958=CARTESIAN_POINT('',(-22.7097215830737,-9.20207913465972,13.831286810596));
#959=CARTESIAN_POINT('',(-22.7010968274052,-9.2076397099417,13.8020734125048));
#960=CARTESIAN_POINT('',(-22.6798306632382,-9.22121664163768,13.74482497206));
#961=CARTESIAN_POINT('',(-22.6670866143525,-9.229295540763,13.7168434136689));
#962=CARTESIAN_POINT('',(-22.6381865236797,-9.24738287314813,13.6634116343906));
#963=CARTESIAN_POINT('',(-22.6220319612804,-9.25739046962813,13.6379603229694));
#964=CARTESIAN_POINT('',(-22.5923770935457,-9.27548597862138,13.597460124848));
#965=CARTESIAN_POINT('',(-22.579645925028,-9.2831842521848,13.5816615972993));
#966=CARTESIAN_POINT('',(-22.5529682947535,-9.29913893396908,13.5514350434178));
#967=CARTESIAN_POINT('',(-22.5390216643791,-9.30739541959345,13.5370072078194));
#968=CARTESIAN_POINT('',(-22.5245249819,-9.31587460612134,13.5232805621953));
#969=B_SPLINE_CURVE_WITH_KNOTS('',3,(#891,#892,#893,#894,#895,#896,#897,#898,#899,#900,#901,
#902,#903,#904,#905,#906,#907,#908,#909,#910,#911,#912,#913,#914,#915,#916,#917,#918,#919,#920,
#921,#922,#923,#924,#925,#926,#927,#928,#929,#930,#931,#932,#933,#934,#935,#936,#937,#938,#939,
#940,#941,#942,#943,#944,#945,#946,#947,#948,#949,#950,#951,#952,#953,#954,#955,#956,#957,#958,
#959,#960,#961,#962,#963,#964,#965,#966,#967,#968),.UNSPECIFIED.,.T.,.F.,(4,2,2,2,2,2,2,2,2,2,2,
2,2,2,2,2,2,2,2,2,2,2,2,2,2,2,2,2,2,2,2,2,2,2,2,2,2,2,4),(0.,0.15427419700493,0.308966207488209,
0.44697486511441,0.58484149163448,0.726489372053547,0.868118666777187,0.99961694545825,
1.13102519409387,1.25017831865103,1.36927860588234,1.48018445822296,1.59106347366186,
1.69798026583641,1.80488692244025,1.91085626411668,2.01682764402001,2.1243515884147,
2.23188945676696,2.34367333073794,2.45548585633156,2.57472140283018,2.69400086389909,
2.82362151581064,2.95329300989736,3.09315386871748,3.23312455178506,3.37489912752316,
3.51639283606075,3.61768524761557,3.71888943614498,3.82064903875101,3.92237141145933,
4.01483642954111,4.1073296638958,4.20233267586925,4.29729456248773,4.36231455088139,
4.42734357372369),.UNSPECIFIED.);
#970=CARTESIAN_POINT('',(-22.5245249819,-9.31587460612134,13.5232805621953));
#971=VERTEX_POINT('',#970);
#972=EDGE_CURVE('E925',#971,#971,#969,.T.);
#973=ORIENTED_EDGE('',*,*,#972,.F.);
#974=EDGE_LOOP('',(#973));
#975=FACE_BOUND('',#974,.T.);
#976=ADVANCED_FACE('F942',(#890,#975),#887,.F.);
#977=CARTESIAN_POINT('',(22.,-10.5,-14.));
#978=DIRECTION('',(0.,1.,0.));
#979=DIRECTION('',(0.,0.,1.));
#980=AXIS2_PLACEMENT_3D('',#977,#978,#979);
#981=PLANE('',#980);
#982=CARTESIAN_POINT('',(22.,-10.5,-14.));
#983=DIRECTION('',(0.,1.,0.));
#984=DIRECTION('',(0.,0.,1.));
#985=AXIS2_PLACEMENT_3D('',#982,#983,#984);
#986=CIRCLE('',#985,0.290225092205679);
#987=CARTESIAN_POINT('',(22.,-10.5,-13.7097749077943));
#988=VERTEX_POINT('',#987);
#989=EDGE_CURVE('E932',#988,#988,#986,.F.);
#990=ORIENTED_EDGE('',*,*,#989,.F.);
#991=EDGE_LOOP('',(#990));
#992=FACE_BOUND('',#991,.T.);
#993=ADVANCED_FACE('F947',(#992),#981,.T.);
#994=CARTESIAN_POINT('',(22.,-10.25,-14.));
#995=DIRECTION('',(0.,1.,0.));
#996=DIRECTION('',(0.,0.,1.));
#997=AXIS2_PLACEMENT_3D('',#994,#995,#996);
#998=TOROIDAL_SURFACE('',#997,0.290225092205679,0.25);
#999=ORIENTED_EDGE('',*,*,#989,.T.);
#1000=EDGE_LOOP('',(#999));
#1001=FACE_BOUND('',#1000,.T.);
#1002=CARTESIAN_POINT('',(22.,-10.2934120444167,-14.));
#1003=DIRECTION('',(0.,-1.,0.));
#1004=DIRECTION('',(0.,0.,-1.));
#1005=AXIS2_PLACEMENT_3D('',#1002,#1003,#1004);
#1006=CIRCLE('',#1005,0.536427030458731);
#1007=CARTESIAN_POINT('',(22.,-10.2934120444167,-14.5364270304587));
#1008=VERTEX_POINT('',#1007);
#1009=EDGE_CURVE('E1652',#1008,#1008,#1006,.F.);
#1010=ORIENTED_EDGE('',*,*,#1009,.T.);
#1011=EDGE_LOOP('',(#1010));
#1012=FACE_BOUND('',#1011,.T.);
#1013=ADVANCED_FACE('F1109',(#1001,#1012),#998,.F.);
#1014=CARTESIAN_POINT('',(22.,-10.5,-14.));
#1015=DIRECTION('',(0.,1.,0.));
#1016=DIRECTION('',(0.,0.,1.));
#1017=AXIS2_PLACEMENT_3D('',#1014,#1015,#1016);
#1018=CONICAL_SURFACE('',#1017,0.499999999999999,0.174532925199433);
#1019=ORIENTED_EDGE('',*,*,#1009,.F.);
#1020=EDGE_LOOP('',(#1019));
#1021=FACE_BOUND('',#1020,.T.);
#1022=CARTESIAN_POINT('',(21.5706541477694,-9.74689851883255,-14.4648526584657));
#1023=CARTESIAN_POINT('',(21.6023195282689,-9.73642039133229,-14.4966083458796));
#1024=CARTESIAN_POINT('',(21.637012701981,-9.72458633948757,-14.5249810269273));
#1025=CARTESIAN_POINT('',(21.7106613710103,-9.6984215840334,-14.574075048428));
#1026=CARTESIAN_POINT('',(21.7496256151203,-9.68408571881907,-14.5947802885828));
#1027=CARTESIAN_POINT('',(21.8241928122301,-9.65549989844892,-14.62574330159));
#1028=CARTESIAN_POINT('',(21.8594657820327,-9.64153794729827,-14.6370795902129));
#1029=CARTESIAN_POINT('',(21.9308149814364,-9.61231377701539,-14.6538898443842));
#1030=CARTESIAN_POINT('',(21.9668905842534,-9.59705254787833,-14.6593682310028));
#1031=CARTESIAN_POINT('',(22.0425088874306,-9.56399161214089,-14.6648605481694));
#1032=CARTESIAN_POINT('',(22.0820488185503,-9.54608922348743,-14.6642935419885));
#1033=CARTESIAN_POINT('',(22.1601230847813,-9.50951553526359,-14.6565384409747));
#1034=CARTESIAN_POINT('',(22.1986567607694,-9.49084375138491,-14.649346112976));
#1035=CARTESIAN_POINT('',(22.2767871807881,-9.45177398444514,-14.6278029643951));
#1036=CARTESIAN_POINT('',(22.3162324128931,-9.43135495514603,-14.6129375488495));
#1037=CARTESIAN_POINT('',(22.3919624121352,-9.39094074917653,-14.5761305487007));
#1038=CARTESIAN_POINT('',(22.4282447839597,-9.37094590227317,-14.5541836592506));
#1039=CARTESIAN_POINT('',(22.4969997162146,-9.33204018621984,-14.5031808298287));
#1040=CARTESIAN_POINT('',(22.5294178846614,-9.31314636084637,-14.4740379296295));
#1041=CARTESIAN_POINT('',(22.5885568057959,-9.27791498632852,-14.409181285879));
#1042=CARTESIAN_POINT('',(22.6152887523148,-9.26157243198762,-14.3734807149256));
#1043=CARTESIAN_POINT('',(22.6549333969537,-9.23694599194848,-14.3072581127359));
#1044=CARTESIAN_POINT('',(22.6696142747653,-9.22769192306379,-14.2781491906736));
#1045=CARTESIAN_POINT('',(22.694642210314,-9.21178391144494,-14.2174575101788));
#1046=CARTESIAN_POINT('',(22.7049930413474,-9.2051277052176,-14.1858769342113));
#1047=CARTESIAN_POINT('',(22.7208376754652,-9.19489378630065,-14.1208356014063));
#1048=CARTESIAN_POINT('',(22.7263046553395,-9.19133307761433,-14.0873655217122));
#1049=CARTESIAN_POINT('',(22.7319141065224,-9.18767927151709,-14.0197937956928));
#1050=CARTESIAN_POINT('',(22.7320583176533,-9.18758504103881,-13.9856923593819));
#1051=CARTESIAN_POINT('',(22.7272500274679,-9.19071746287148,-13.9211443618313));
#1052=CARTESIAN_POINT('',(22.7227587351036,-9.19364360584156,-13.8906469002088));
#1053=CARTESIAN_POINT('',(22.709630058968,-9.2021381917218,-13.8309482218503));
#1054=CARTESIAN_POINT('',(22.700992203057,-9.20770693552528,-13.801747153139));
#1055=CARTESIAN_POINT('',(22.6797019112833,-9.22129839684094,-13.7445247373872));
#1056=CARTESIAN_POINT('',(22.6669470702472,-9.2293834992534,-13.7165567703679));
#1057=CARTESIAN_POINT('',(22.6380217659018,-9.2474853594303,-13.663135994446));
#1058=CARTESIAN_POINT('',(22.6218499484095,-9.25750288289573,-13.6376841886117));
#1059=CARTESIAN_POINT('',(22.5841085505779,-9.2805299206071,-13.5861994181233));
#1060=CARTESIAN_POINT('',(22.5620995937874,-9.29376210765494,-13.5605889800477));
#1061=CARTESIAN_POINT('',(22.5149514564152,-9.32154709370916,-13.5132686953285));
#1062=CARTESIAN_POINT('',(22.4898103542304,-9.33610070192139,-13.4915612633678));
#1063=CARTESIAN_POINT('',(22.432501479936,-9.36854584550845,-13.4488891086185));
#1064=CARTESIAN_POINT('',(22.3998637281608,-9.3865863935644,-13.4286669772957));
#1065=CARTESIAN_POINT('',(22.3318747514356,-9.4231043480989,-13.3939891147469));
#1066=CARTESIAN_POINT('',(22.2965219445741,-9.4415820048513,-13.3795367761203));
#1067=CARTESIAN_POINT('',(22.219872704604,-9.48042440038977,-13.3553862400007));
#1068=CARTESIAN_POINT('',(22.1783487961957,-9.50077487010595,-13.346379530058));
#1069=CARTESIAN_POINT('',(22.093953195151,-9.54065398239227,-13.3361170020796));
#1070=CARTESIAN_POINT('',(22.0510812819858,-9.56018248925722,-13.3348624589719));
#1071=CARTESIAN_POINT('',(21.9651668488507,-9.59786047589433,-13.3404504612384));
#1072=CARTESIAN_POINT('',(21.9221241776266,-9.61600808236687,-13.3473038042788));
#1073=CARTESIAN_POINT('',(21.8374147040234,-9.65037564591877,-13.369346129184));
#1074=CARTESIAN_POINT('',(21.7957472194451,-9.6665965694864,-13.3845309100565));
#1075=CARTESIAN_POINT('',(21.718637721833,-9.6955137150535,-13.4216491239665));
#1076=CARTESIAN_POINT('',(21.6829636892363,-9.70838639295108,-13.442961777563));
#1077=CARTESIAN_POINT('',(21.6156975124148,-9.73189084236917,-13.4922363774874));
#1078=CARTESIAN_POINT('',(21.5841028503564,-9.74252399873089,-13.5201941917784));
#1079=CARTESIAN_POINT('',(21.5290933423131,-9.76052900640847,-13.5791567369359));
#1080=CARTESIAN_POINT('',(21.5051937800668,-9.7681106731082,-13.6096459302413));
#1081=CARTESIAN_POINT('',(21.4629366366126,-9.78124542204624,-13.6746391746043));
#1082=CARTESIAN_POINT('',(21.4445767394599,-9.78679935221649,-13.7091415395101));
#1083=CARTESIAN_POINT('',(21.4151717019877,-9.79557194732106,-13.7787568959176));
#1084=CARTESIAN_POINT('',(21.4037317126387,-9.79891794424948,-13.8136875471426));
#1085=CARTESIAN_POINT('',(21.3868424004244,-9.80382625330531,-13.8850867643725));
#1086=CARTESIAN_POINT('',(21.3813915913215,-9.8053890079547,-13.9215549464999));
#1087=CARTESIAN_POINT('',(21.3767695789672,-9.80671518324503,-13.9937444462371));
#1088=CARTESIAN_POINT('',(21.3774033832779,-9.80653447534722,-14.0294524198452));
#1089=CARTESIAN_POINT('',(21.3844605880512,-9.80450643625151,-14.1002490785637));
#1090=CARTESIAN_POINT('',(21.3908847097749,-9.80265889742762,-14.1353376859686));
#1091=CARTESIAN_POINT('',(21.4092331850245,-9.79730671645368,-14.2037086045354));
#1092=CARTESIAN_POINT('',(21.4211286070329,-9.79381078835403,-14.2369994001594));
#1093=CARTESIAN_POINT('',(21.4499714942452,-9.78516536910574,-14.3010502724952));
#1094=CARTESIAN_POINT('',(21.4669138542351,-9.78001754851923,-14.3318128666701));
#1095=CARTESIAN_POINT('',(21.4984418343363,-9.77020324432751,-14.3797219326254));
#1096=CARTESIAN_POINT('',(21.5117371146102,-9.76601195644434,-14.3978322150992));
#1097=CARTESIAN_POINT('',(21.5399912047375,-9.7569578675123,-14.4325234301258));
#1098=CARTESIAN_POINT('',(21.5549503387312,-9.75209493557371,-14.4491040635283));
#1099=CARTESIAN_POINT('',(21.5706541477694,-9.74689851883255,-14.4648526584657));
#1100=B_SPLINE_CURVE_WITH_KNOTS('',3,(#1022,#1023,#1024,#1025,#1026,#1027,#1028,#1029,#1030,
#1031,#1032,#1033,#1034,#1035,#1036,#1037,#1038,#1039,#1040,#1041,#1042,#1043,#1044,#1045,#1046,
#1047,#1048,#1049,#1050,#1051,#1052,#1053,#1054,#1055,#1056,#1057,#1058,#1059,#1060,#1061,#1062,
#1063,#1064,#1065,#1066,#1067,#1068,#1069,#1070,#1071,#1072,#1073,#1074,#1075,#1076,#1077,#1078,
#1079,#1080,#1081,#1082,#1083,#1084,#1085,#1086,#1087,#1088,#1089,#1090,#1091,#1092,#1093,#1094,
#1095,#1096,#1097,#1098,#1099),.UNSPECIFIED.,.T.,.F.,(4,2,2,2,2,2,2,2,2,2,2,2,2,2,2,2,2,2,2,2,2,
2,2,2,2,2,2,2,2,2,2,2,2,2,2,2,2,2,4),(0.,0.138044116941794,0.276376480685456,0.394682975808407,
0.512900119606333,0.64257234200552,0.772327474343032,0.912203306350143,1.05218416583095,
1.1939473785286,1.33542888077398,1.43668891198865,1.53786051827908,1.6395844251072,
1.74127508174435,1.83373991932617,1.92621528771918,2.0211955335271,2.11621349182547,
2.22460681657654,2.33306697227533,2.45981776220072,2.58664297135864,2.7273174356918,
2.86801503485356,3.00890021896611,3.14971442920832,3.27951424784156,3.40923356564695,
3.527041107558,3.64479932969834,3.75497573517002,3.8651247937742,3.9717560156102,
4.07840052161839,4.184487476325,4.29046748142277,4.35891432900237,4.42737453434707),.UNSPECIFIED.);
#1101=CARTESIAN_POINT('',(21.5706541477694,-9.74689851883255,-14.4648526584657));
#1102=VERTEX_POINT('',#1101);
#1103=EDGE_CURVE('E1651',#1102,#1102,#1100,.T.);
#1104=ORIENTED_EDGE('',*,*,#1103,.F.);
#1105=EDGE_LOOP('',(#1104));
#1106=FACE_BOUND('',#1105,.T.);
#1107=ADVANCED_FACE('F1116',(#1021,#1106),#1018,.F.);
#1108=CARTESIAN_POINT('',(22.,-10.5,14.));
#1109=DIRECTION('',(0.,1.,0.));
#1110=DIRECTION('',(0.,0.,1.));
#1111=AXIS2_PLACEMENT_3D('',#1108,#1109,#1110);
#1112=PLANE('',#1111);
#1113=CARTESIAN_POINT('',(22.,-10.5,14.));
#1114=DIRECTION('',(0.,1.,0.));
#1115=DIRECTION('',(0.,0.,1.));
#1116=AXIS2_PLACEMENT_3D('',#1113,#1114,#1115);
#1117=CIRCLE('',#1116,0.290225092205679);
#1118=CARTESIAN_POINT('',(22.,-10.5,14.2902250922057));
#1119=VERTEX_POINT('',#1118);
#1120=EDGE_CURVE('E1648',#1119,#1119,#1117,.F.);
#1121=ORIENTED_EDGE('',*,*,#1120,.F.);
#1122=EDGE_LOOP('',(#1121));
#1123=FACE_BOUND('',#1122,.T.);
#1124=ADVANCED_FACE('F1123',(#1123),#1112,.T.);
#1125=CARTESIAN_POINT('',(22.,-10.25,14.));
#1126=DIRECTION('',(0.,1.,0.));
#1127=DIRECTION('',(0.,0.,1.));
#1128=AXIS2_PLACEMENT_3D('',#1125,#1126,#1127);
#1129=TOROIDAL_SURFACE('',#1128,0.290225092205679,0.25);
#1130=ORIENTED_EDGE('',*,*,#1120,.T.);
#1131=EDGE_LOOP('',(#1130));
#1132=FACE_BOUND('',#1131,.T.);
#1133=CARTESIAN_POINT('',(22.,-10.2934120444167,14.));
#1134=DIRECTION('',(0.,-1.,0.));
#1135=DIRECTION('',(0.,0.,-1.));
#1136=AXIS2_PLACEMENT_3D('',#1133,#1134,#1135);
#1137=CIRCLE('',#1136,0.536427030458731);
#1138=CARTESIAN_POINT('',(22.,-10.2934120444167,13.4635729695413));
#1139=VERTEX_POINT('',#1138);
#1140=EDGE_CURVE('E1645',#1139,#1139,#1137,.F.);
#1141=ORIENTED_EDGE('',*,*,#1140,.T.);
#1142=EDGE_LOOP('',(#1141));
#1143=FACE_BOUND('',#1142,.T.);
#1144=ADVANCED_FACE('F1131',(#1132,#1143),#1129,.F.);
#1145=CARTESIAN_POINT('',(22.,-10.5,14.));
#1146=DIRECTION('',(0.,1.,0.));
#1147=DIRECTION('',(0.,0.,1.));
#1148=AXIS2_PLACEMENT_3D('',#1145,#1146,#1147);
#1149=CONICAL_SURFACE('',#1148,0.499999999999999,0.174532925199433);
#1150=ORIENTED_EDGE('',*,*,#1140,.F.);
#1151=EDGE_LOOP('',(#1150));
#1152=FACE_BOUND('',#1151,.T.);
#1153=CARTESIAN_POINT('',(21.5669156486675,-9.74813388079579,13.5389271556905));
#1154=CARTESIAN_POINT('',(21.5983361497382,-9.73776424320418,13.5069115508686));
#1155=CARTESIAN_POINT('',(21.6328165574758,-9.72603652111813,13.478255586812));
#1156=CARTESIAN_POINT('',(21.7061079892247,-9.70007523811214,13.428568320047));
#1157=CARTESIAN_POINT('',(21.7449278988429,-9.68583649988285,13.4075530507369));
#1158=CARTESIAN_POINT('',(21.8192350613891,-9.65743811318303,13.3760284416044));
#1159=CARTESIAN_POINT('',(21.8543807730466,-9.64357074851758,13.3644328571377));
#1160=CARTESIAN_POINT('',(21.9255174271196,-9.61452676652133,13.347086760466));
#1161=CARTESIAN_POINT('',(21.9615077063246,-9.59935115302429,13.3413318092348));
#1162=CARTESIAN_POINT('',(22.0369790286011,-9.56646129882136,13.3352477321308));
#1163=CARTESIAN_POINT('',(22.0764614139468,-9.54864344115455,13.3354964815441));
#1164=CARTESIAN_POINT('',(22.1544682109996,-9.51221934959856,13.3426008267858));
#1165=CARTESIAN_POINT('',(22.1929919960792,-9.49361262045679,13.3494606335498));
#1166=CARTESIAN_POINT('',(22.2711808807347,-9.45463699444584,13.3703070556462));
#1167=CARTESIAN_POINT('',(22.3106969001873,-9.43424472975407,13.3848124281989));
#1168=CARTESIAN_POINT('',(22.386625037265,-9.3938449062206,13.4208935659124));
#1169=CARTESIAN_POINT('',(22.4230347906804,-9.3738376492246,13.442474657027));
#1170=CARTESIAN_POINT('',(22.4921974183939,-9.33480706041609,13.4927979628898));
#1171=CARTESIAN_POINT('',(22.5248864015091,-9.31580327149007,13.5216438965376));
#1172=CARTESIAN_POINT('',(22.5846242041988,-9.28029476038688,13.5859436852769));
#1173=CARTESIAN_POINT('',(22.6116838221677,-9.26378527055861,13.6213846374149));
#1174=CARTESIAN_POINT('',(22.6519992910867,-9.23878479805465,13.6873025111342));
#1175=CARTESIAN_POINT('',(22.6669959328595,-9.22934548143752,13.7163610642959));
#1176=CARTESIAN_POINT('',(22.6926563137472,-9.21305511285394,13.7770121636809));
#1177=CARTESIAN_POINT('',(22.7033238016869,-9.20620182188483,13.8086024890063));
#1178=CARTESIAN_POINT('',(22.7197908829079,-9.19557341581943,13.8737365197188));
#1179=CARTESIAN_POINT('',(22.7255628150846,-9.19181579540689,13.9072901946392));
#1180=CARTESIAN_POINT('',(22.7317449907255,-9.18778989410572,13.9750956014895));
#1181=CARTESIAN_POINT('',(22.732157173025,-9.18752035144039,14.0093470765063));
#1182=CARTESIAN_POINT('',(22.7278134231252,-9.1903505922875,14.0741353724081));
#1183=CARTESIAN_POINT('',(22.7235371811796,-9.19313765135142,14.1047200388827));
#1184=CARTESIAN_POINT('',(22.7108097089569,-9.20137685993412,14.1646275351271));
#1185=CARTESIAN_POINT('',(22.7023580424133,-9.20682928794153,14.1939502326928));
#1186=CARTESIAN_POINT('',(22.6814503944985,-9.22018719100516,14.2513349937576));
#1187=CARTESIAN_POINT('',(22.6689054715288,-9.22814700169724,14.2793515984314));
#1188=CARTESIAN_POINT('',(22.6403895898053,-9.24601289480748,14.3328997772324));
#1189=CARTESIAN_POINT('',(22.624417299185,-9.2559197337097,14.3584303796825));
#1190=CARTESIAN_POINT('',(22.5871224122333,-9.27870746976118,14.4100657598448));
#1191=CARTESIAN_POINT('',(22.565364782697,-9.29181033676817,14.4357574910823));
#1192=CARTESIAN_POINT('',(22.5187132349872,-9.31935396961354,14.4832802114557));
#1193=CARTESIAN_POINT('',(22.4938173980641,-9.33379555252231,14.5051088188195));
#1194=CARTESIAN_POINT('',(22.4370209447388,-9.36602388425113,14.5480941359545));
#1195=CARTESIAN_POINT('',(22.4046476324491,-9.3839634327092,14.5685134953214));
#1196=CARTESIAN_POINT('',(22.3371696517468,-9.42030648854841,14.603637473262));
#1197=CARTESIAN_POINT('',(22.3020633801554,-9.43871026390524,14.6183387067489));
#1198=CARTESIAN_POINT('',(22.2258222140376,-9.47747006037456,14.6431005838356));
#1199=CARTESIAN_POINT('',(22.1844516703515,-9.49781484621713,14.6524606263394));
#1200=CARTESIAN_POINT('',(22.1003107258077,-9.53771564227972,14.6634700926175));
#1201=CARTESIAN_POINT('',(22.0575400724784,-9.55727150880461,14.6651181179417));
#1202=CARTESIAN_POINT('',(21.9716472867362,-9.59508606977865,14.6603497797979));
#1203=CARTESIAN_POINT('',(21.9285244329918,-9.61333929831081,14.6539013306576));
#1204=CARTESIAN_POINT('',(21.8435786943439,-9.64793696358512,14.632653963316));
#1205=CARTESIAN_POINT('',(21.8017551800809,-9.66428233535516,14.6178591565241));
#1206=CARTESIAN_POINT('',(21.7242213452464,-9.69346845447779,14.5814370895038));
#1207=CARTESIAN_POINT('',(21.6882882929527,-9.70648218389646,14.5604239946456));
#1208=CARTESIAN_POINT('',(21.6204506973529,-9.7302675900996,14.5116878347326));
#1209=CARTESIAN_POINT('',(21.588543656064,-9.74104065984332,14.4839689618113));
#1210=CARTESIAN_POINT('',(21.5329106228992,-9.75930303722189,14.4254018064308));
#1211=CARTESIAN_POINT('',(21.5087016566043,-9.76700348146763,14.395077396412));
#1212=CARTESIAN_POINT('',(21.4658038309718,-9.78036878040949,14.3303482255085));
#1213=CARTESIAN_POINT('',(21.4471126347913,-9.78603449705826,14.2959452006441));
#1214=CARTESIAN_POINT('',(21.4170739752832,-9.79501116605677,14.2264858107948));
#1215=CARTESIAN_POINT('',(21.4053269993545,-9.79845161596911,14.1916184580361));
#1216=CARTESIAN_POINT('',(21.3878212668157,-9.80354415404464,14.1202882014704));
#1217=CARTESIAN_POINT('',(21.3820609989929,-9.80519669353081,14.0838257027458));
#1218=CARTESIAN_POINT('',(21.3768420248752,-9.80669459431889,14.011618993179));
#1219=CARTESIAN_POINT('',(21.3771835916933,-9.80659723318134,13.9758902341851));
#1220=CARTESIAN_POINT('',(21.3836679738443,-9.80473454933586,13.9050015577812));
#1221=CARTESIAN_POINT('',(21.3898114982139,-9.80296902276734,13.8698417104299));
#1222=CARTESIAN_POINT('',(21.407616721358,-9.79778070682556,13.8013029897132));
#1223=CARTESIAN_POINT('',(21.41924609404,-9.79436762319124,13.7679149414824));
#1224=CARTESIAN_POINT('',(21.4475813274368,-9.78588814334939,13.7036268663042));
#1225=CARTESIAN_POINT('',(21.4642820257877,-9.78082342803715,13.6727243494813));
#1226=CARTESIAN_POINT('',(21.4954265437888,-9.77114892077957,13.6245740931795));
#1227=CARTESIAN_POINT('',(21.5085689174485,-9.76701523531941,13.6063716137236));
#1228=CARTESIAN_POINT('',(21.5365287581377,-9.75807689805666,13.5714799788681));
#1229=CARTESIAN_POINT('',(21.5513465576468,-9.75327211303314,13.5547911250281));
#1230=CARTESIAN_POINT('',(21.5669156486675,-9.74813388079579,13.5389271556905));
#1231=B_SPLINE_CURVE_WITH_KNOTS('',3,(#1153,#1154,#1155,#1156,#1157,#1158,#1159,#1160,#1161,
#1162,#1163,#1164,#1165,#1166,#1167,#1168,#1169,#1170,#1171,#1172,#1173,#1174,#1175,#1176,#1177,
#1178,#1179,#1180,#1181,#1182,#1183,#1184,#1185,#1186,#1187,#1188,#1189,#1190,#1191,#1192,#1193,
#1194,#1195,#1196,#1197,#1198,#1199,#1200,#1201,#1202,#1203,#1204,#1205,#1206,#1207,#1208,#1209,
#1210,#1211,#1212,#1213,#1214,#1215,#1216,#1217,#1218,#1219,#1220,#1221,#1222,#1223,#1224,#1225,
#1226,#1227,#1228,#1229,#1230),.UNSPECIFIED.,.T.,.F.,(4,2,2,2,2,2,2,2,2,2,2,2,2,2,2,2,2,2,2,2,2,
2,2,2,2,2,2,2,2,2,2,2,2,2,2,2,2,2,4),(0.,0.138006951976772,0.276301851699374,0.394394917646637,
0.512398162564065,0.64180120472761,0.771286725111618,0.910970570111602,1.05075979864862,
1.19267072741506,1.334306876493,1.436003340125,1.53761155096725,1.63979011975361,
1.74193172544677,1.83452158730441,1.92712112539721,2.02188411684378,2.11668399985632,
2.22465496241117,2.33269226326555,2.45899260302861,2.58536759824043,2.72583988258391,
2.8663376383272,3.00739393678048,3.14838081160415,3.27850631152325,3.40855067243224,
3.52660956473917,3.6446183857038,3.75492922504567,3.86521221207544,3.97189219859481,
4.07858522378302,4.18465725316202,4.29062166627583,4.35899154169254,4.42737500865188),.UNSPECIFIED.);
#1232=CARTESIAN_POINT('',(21.5669156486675,-9.74813388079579,13.5389271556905));
#1233=VERTEX_POINT('',#1232);
#1234=EDGE_CURVE('E924',#1233,#1233,#1231,.T.);
#1235=ORIENTED_EDGE('',*,*,#1234,.F.);
#1236=EDGE_LOOP('',(#1235));
#1237=FACE_BOUND('',#1236,.T.);
#1238=ADVANCED_FACE('F1139',(#1152,#1237),#1149,.F.);
#1239=CARTESIAN_POINT('',(-15.,-9.15331193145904,17.5));
#1240=DIRECTION('',(0.,0.,-1.));
#1241=DIRECTION('',(-1.,0.,0.));
#1242=AXIS2_PLACEMENT_3D('',#1239,#1240,#1241);
#1243=CYLINDRICAL_SURFACE('',#1242,1.5);
#1244=DIRECTION('',(0.,0.,-1.));
#1245=VECTOR('',#1244,1.);
#1246=CARTESIAN_POINT('',(-16.1538461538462,-8.19485533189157,17.5));
#1247=LINE('',#1246,#1245);
#1248=CARTESIAN_POINT('',(-16.1538461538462,-8.19485533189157,15.));
#1249=VERTEX_POINT('',#1248);
#1250=CARTESIAN_POINT('',(-16.1538461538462,-8.19485533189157,-15.));
#1251=VERTEX_POINT('',#1250);
#1252=EDGE_CURVE('E913',#1249,#1251,#1247,.T.);
#1253=ORIENTED_EDGE('',*,*,#1252,.F.);
#1254=CARTESIAN_POINT('',(-15.,-9.15331193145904,15.));
#1255=DIRECTION('',(0.,0.,-1.));
#1256=DIRECTION('',(-1.,0.,0.));
#1257=AXIS2_PLACEMENT_3D('',#1254,#1255,#1256);
#1258=CIRCLE('',#1257,1.5);
#1259=CARTESIAN_POINT('',(-13.8461538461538,-8.19485533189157,15.));
#1260=VERTEX_POINT('',#1259);
#1261=EDGE_CURVE('E1629',#1260,#1249,#1258,.F.);
#1262=ORIENTED_EDGE('',*,*,#1261,.F.);
#1263=DIRECTION('',(0.,0.,-1.));
#1264=VECTOR('',#1263,1.);
#1265=CARTESIAN_POINT('',(-13.8461538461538,-8.19485533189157,17.5));
#1266=LINE('',#1265,#1264);
#1267=CARTESIAN_POINT('',(-13.8461538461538,-8.19485533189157,-15.));
#1268=VERTEX_POINT('',#1267);
#1269=EDGE_CURVE('E1632',#1260,#1268,#1266,.T.);
#1270=ORIENTED_EDGE('',*,*,#1269,.T.);
#1271=CARTESIAN_POINT('',(-15.,-9.15331193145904,-15.));
#1272=DIRECTION('',(0.,0.,-1.));
#1273=DIRECTION('',(-1.,0.,0.));
#1274=AXIS2_PLACEMENT_3D('',#1271,#1272,#1273);
#1275=CIRCLE('',#1274,1.5);
#1276=EDGE_CURVE('E923',#1251,#1268,#1275,.T.);
#1277=ORIENTED_EDGE('',*,*,#1276,.F.);
#1278=EDGE_LOOP('',(#1253,#1262,#1270,#1277));
#1279=FACE_BOUND('',#1278,.T.);
#1280=ADVANCED_FACE('F1147',(#1279),#1243,.T.);
#1281=CARTESIAN_POINT('',(-10.,-5.,17.5));
#1282=DIRECTION('',(0.,0.,-1.));
#1283=DIRECTION('',(-1.,0.,0.));
#1284=AXIS2_PLACEMENT_3D('',#1281,#1282,#1283);
#1285=CYLINDRICAL_SURFACE('',#1284,5.);
#1286=ORIENTED_EDGE('',*,*,#1269,.F.);
#1287=CARTESIAN_POINT('',(-10.,-5.,15.));
#1288=DIRECTION('',(0.,0.,-1.));
#1289=DIRECTION('',(-1.,0.,0.));
#1290=AXIS2_PLACEMENT_3D('',#1287,#1288,#1289);
#1291=CIRCLE('',#1290,5.);
#1292=CARTESIAN_POINT('',(-6.15384615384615,-8.19485533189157,15.));
#1293=VERTEX_POINT('',#1292);
#1294=EDGE_CURVE('E1622',#1293,#1260,#1291,.T.);
#1295=ORIENTED_EDGE('',*,*,#1294,.F.);
#1296=DIRECTION('',(0.,0.,-1.));
#1297=VECTOR('',#1296,1.);
#1298=CARTESIAN_POINT('',(-6.15384615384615,-8.19485533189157,17.5));
#1299=LINE('',#1298,#1297);
#1300=CARTESIAN_POINT('',(-6.15384615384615,-8.19485533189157,-15.));
#1301=VERTEX_POINT('',#1300);
#1302=EDGE_CURVE('E1626',#1293,#1301,#1299,.T.);
#1303=ORIENTED_EDGE('',*,*,#1302,.T.);
#1304=CARTESIAN_POINT('',(-10.,-5.,-15.));
#1305=DIRECTION('',(0.,0.,-1.));
#1306=DIRECTION('',(-1.,0.,0.));
#1307=AXIS2_PLACEMENT_3D('',#1304,#1305,#1306);
#1308=CIRCLE('',#1307,5.);
#1309=EDGE_CURVE('E1631',#1268,#1301,#1308,.F.);
#1310=ORIENTED_EDGE('',*,*,#1309,.F.);
#1311=EDGE_LOOP('',(#1286,#1295,#1303,#1310));
#1312=FACE_BOUND('',#1311,.T.);
#1313=ADVANCED_FACE('F1155',(#1312),#1285,.F.);
#1314=CARTESIAN_POINT('',(-5.,-9.15331193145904,17.5));
#1315=DIRECTION('',(0.,0.,-1.));
#1316=DIRECTION('',(-1.,0.,0.));
#1317=AXIS2_PLACEMENT_3D('',#1314,#1315,#1316);
#1318=CYLINDRICAL_SURFACE('',#1317,1.5);
#1319=ORIENTED_EDGE('',*,*,#1302,.F.);
#1320=CARTESIAN_POINT('',(-5.,-9.15331193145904,15.));
#1321=DIRECTION('',(0.,0.,-1.));
#1322=DIRECTION('',(-1.,0.,0.));
#1323=AXIS2_PLACEMENT_3D('',#1320,#1321,#1322);
#1324=CIRCLE('',#1323,1.5);
#1325=CARTESIAN_POINT('',(-3.84615384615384,-8.19485533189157,15.));
#1326=VERTEX_POINT('',#1325);
#1327=EDGE_CURVE('E1614',#1326,#1293,#1324,.F.);
#1328=ORIENTED_EDGE('',*,*,#1327,.F.);
#1329=DIRECTION('',(0.,0.,-1.));
#1330=VECTOR('',#1329,1.);
#1331=CARTESIAN_POINT('',(-3.84615384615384,-8.19485533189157,17.5));
#1332=LINE('',#1331,#1330);
#1333=CARTESIAN_POINT('',(-3.84615384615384,-8.19485533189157,-15.));
#1334=VERTEX_POINT('',#1333);
#1335=EDGE_CURVE('E1618',#1326,#1334,#1332,.T.);
#1336=ORIENTED_EDGE('',*,*,#1335,.T.);
#1337=CARTESIAN_POINT('',(-5.,-9.15331193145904,-15.));
#1338=DIRECTION('',(0.,0.,-1.));
#1339=DIRECTION('',(-1.,0.,0.));
#1340=AXIS2_PLACEMENT_3D('',#1337,#1338,#1339);
#1341=CIRCLE('',#1340,1.5);
#1342=EDGE_CURVE('E1625',#1301,#1334,#1341,.T.);
#1343=ORIENTED_EDGE('',*,*,#1342,.F.);
#1344=EDGE_LOOP('',(#1319,#1328,#1336,#1343));
#1345=FACE_BOUND('',#1344,.T.);
#1346=ADVANCED_FACE('F1163',(#1345),#1318,.T.);
#1347=CARTESIAN_POINT('',(0.,-5.,17.5));
#1348=DIRECTION('',(0.,0.,-1.));
#1349=DIRECTION('',(-1.,0.,0.));
#1350=AXIS2_PLACEMENT_3D('',#1347,#1348,#1349);
#1351=CYLINDRICAL_SURFACE('',#1350,5.);
#1352=ORIENTED_EDGE('',*,*,#1335,.F.);
#1353=CARTESIAN_POINT('',(0.,-5.,15.));
#1354=DIRECTION('',(0.,0.,-1.));
#1355=DIRECTION('',(-1.,0.,0.));
#1356=AXIS2_PLACEMENT_3D('',#1353,#1354,#1355);
#1357=CIRCLE('',#1356,5.);
#1358=CARTESIAN_POINT('',(3.84615384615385,-8.19485533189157,15.));
#1359=VERTEX_POINT('',#1358);
#1360=EDGE_CURVE('E1605',#1359,#1326,#1357,.T.);
#1361=ORIENTED_EDGE('',*,*,#1360,.F.);
#1362=DIRECTION('',(0.,0.,-1.));
#1363=VECTOR('',#1362,1.);
#1364=CARTESIAN_POINT('',(3.84615384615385,-8.19485533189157,17.5));
#1365=LINE('',#1364,#1363);
#1366=CARTESIAN_POINT('',(3.84615384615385,-8.19485533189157,-15.));
#1367=VERTEX_POINT('',#1366);
#1368=EDGE_CURVE('E1609',#1359,#1367,#1365,.T.);
#1369=ORIENTED_EDGE('',*,*,#1368,.T.);
#1370=CARTESIAN_POINT('',(0.,-5.,-15.));
#1371=DIRECTION('',(0.,0.,-1.));
#1372=DIRECTION('',(-1.,0.,0.));
#1373=AXIS2_PLACEMENT_3D('',#1370,#1371,#1372);
#1374=CIRCLE('',#1373,5.);
#1375=EDGE_CURVE('E1617',#1334,#1367,#1374,.F.);
#1376=ORIENTED_EDGE('',*,*,#1375,.F.);
#1377=EDGE_LOOP('',(#1352,#1361,#1369,#1376));
#1378=FACE_BOUND('',#1377,.T.);
#1379=ADVANCED_FACE('F1171',(#1378),#1351,.F.);
#1380=CARTESIAN_POINT('',(5.,-9.15331193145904,17.5));
#1381=DIRECTION('',(0.,0.,-1.));
#1382=DIRECTION('',(-1.,0.,0.));
#1383=AXIS2_PLACEMENT_3D('',#1380,#1381,#1382);
#1384=CYLINDRICAL_SURFACE('',#1383,1.5);
#1385=ORIENTED_EDGE('',*,*,#1368,.F.);
#1386=CARTESIAN_POINT('',(5.,-9.15331193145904,15.));
#1387=DIRECTION('',(0.,0.,-1.));
#1388=DIRECTION('',(-1.,0.,0.));
#1389=AXIS2_PLACEMENT_3D('',#1386,#1387,#1388);
#1390=CIRCLE('',#1389,1.5);
#1391=CARTESIAN_POINT('',(6.15384615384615,-8.19485533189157,15.));
#1392=VERTEX_POINT('',#1391);
#1393=EDGE_CURVE('E1597',#1392,#1359,#1390,.F.);
#1394=ORIENTED_EDGE('',*,*,#1393,.F.);
#1395=DIRECTION('',(0.,0.,-1.));
#1396=VECTOR('',#1395,1.);
#1397=CARTESIAN_POINT('',(6.15384615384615,-8.19485533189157,17.5));
#1398=LINE('',#1397,#1396);
#1399=CARTESIAN_POINT('',(6.15384615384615,-8.19485533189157,-15.));
#1400=VERTEX_POINT('',#1399);
#1401=EDGE_CURVE('E1601',#1392,#1400,#1398,.T.);
#1402=ORIENTED_EDGE('',*,*,#1401,.T.);
#1403=CARTESIAN_POINT('',(5.,-9.15331193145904,-15.));
#1404=DIRECTION('',(0.,0.,-1.));
#1405=DIRECTION('',(-1.,0.,0.));
#1406=AXIS2_PLACEMENT_3D('',#1403,#1404,#1405);
#1407=CIRCLE('',#1406,1.5);
#1408=EDGE_CURVE('E1608',#1367,#1400,#1407,.T.);
#1409=ORIENTED_EDGE('',*,*,#1408,.F.);
#1410=EDGE_LOOP('',(#1385,#1394,#1402,#1409));
#1411=FACE_BOUND('',#1410,.T.);
#1412=ADVANCED_FACE('F1179',(#1411),#1384,.T.);
#1413=CARTESIAN_POINT('',(10.,-5.,17.5));
#1414=DIRECTION('',(0.,0.,-1.));
#1415=DIRECTION('',(-1.,0.,0.));
#1416=AXIS2_PLACEMENT_3D('',#1413,#1414,#1415);
#1417=CYLINDRICAL_SURFACE('',#1416,5.);
#1418=ORIENTED_EDGE('',*,*,#1401,.F.);
#1419=CARTESIAN_POINT('',(10.,-5.,15.));
#1420=DIRECTION('',(0.,0.,-1.));
#1421=DIRECTION('',(-1.,0.,0.));
#1422=AXIS2_PLACEMENT_3D('',#1419,#1420,#1421);
#1423=CIRCLE('',#1422,5.);
#1424=CARTESIAN_POINT('',(13.8461538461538,-8.19485533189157,15.));
#1425=VERTEX_POINT('',#1424);
#1426=EDGE_CURVE('E1589',#1425,#1392,#1423,.T.);
#1427=ORIENTED_EDGE('',*,*,#1426,.F.);
#1428=DIRECTION('',(0.,0.,-1.));
#1429=VECTOR('',#1428,1.);
#1430=CARTESIAN_POINT('',(13.8461538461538,-8.19485533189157,17.5));
#1431=LINE('',#1430,#1429);
#1432=CARTESIAN_POINT('',(13.8461538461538,-8.19485533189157,-15.));
#1433=VERTEX_POINT('',#1432);
#1434=EDGE_CURVE('E1593',#1425,#1433,#1431,.T.);
#1435=ORIENTED_EDGE('',*,*,#1434,.T.);
#1436=CARTESIAN_POINT('',(10.,-5.,-15.));
#1437=DIRECTION('',(0.,0.,-1.));
#1438=DIRECTION('',(-1.,0.,0.));
#1439=AXIS2_PLACEMENT_3D('',#1436,#1437,#1438);
#1440=CIRCLE('',#1439,5.);
#1441=EDGE_CURVE('E1600',#1400,#1433,#1440,.F.);
#1442=ORIENTED_EDGE('',*,*,#1441,.F.);
#1443=EDGE_LOOP('',(#1418,#1427,#1435,#1442));
#1444=FACE_BOUND('',#1443,.T.);
#1445=ADVANCED_FACE('F1187',(#1444),#1417,.F.);
#1446=CARTESIAN_POINT('',(15.,-9.15331193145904,17.5));
#1447=DIRECTION('',(0.,0.,-1.));
#1448=DIRECTION('',(-1.,0.,0.));
#1449=AXIS2_PLACEMENT_3D('',#1446,#1447,#1448);
#1450=CYLINDRICAL_SURFACE('',#1449,1.5);
#1451=ORIENTED_EDGE('',*,*,#1434,.F.);
#1452=CARTESIAN_POINT('',(15.,-9.15331193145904,15.));
#1453=DIRECTION('',(0.,0.,-1.));
#1454=DIRECTION('',(-1.,0.,0.));
#1455=AXIS2_PLACEMENT_3D('',#1452,#1453,#1454);
#1456=CIRCLE('',#1455,1.5);
#1457=CARTESIAN_POINT('',(16.1538461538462,-8.19485533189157,15.));
#1458=VERTEX_POINT('',#1457);
#1459=EDGE_CURVE('E1584',#1458,#1425,#1456,.F.);
#1460=ORIENTED_EDGE('',*,*,#1459,.F.);
#1461=DIRECTION('',(0.,0.,-1.));
#1462=VECTOR('',#1461,1.);
#1463=CARTESIAN_POINT('',(16.1538461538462,-8.19485533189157,17.5));
#1464=LINE('',#1463,#1462);
#1465=CARTESIAN_POINT('',(16.1538461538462,-8.19485533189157,-15.));
#1466=VERTEX_POINT('',#1465);
#1467=EDGE_CURVE('E1575',#1458,#1466,#1464,.T.);
#1468=ORIENTED_EDGE('',*,*,#1467,.T.);
#1469=CARTESIAN_POINT('',(15.,-9.15331193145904,-15.));
#1470=DIRECTION('',(0.,0.,-1.));
#1471=DIRECTION('',(-1.,0.,0.));
#1472=AXIS2_PLACEMENT_3D('',#1469,#1470,#1471);
#1473=CIRCLE('',#1472,1.5);
#1474=EDGE_CURVE('E1592',#1433,#1466,#1473,.T.);
#1475=ORIENTED_EDGE('',*,*,#1474,.F.);
#1476=EDGE_LOOP('',(#1451,#1460,#1468,#1475));
#1477=FACE_BOUND('',#1476,.T.);
#1478=ADVANCED_FACE('F1195',(#1477),#1450,.T.);
#1479=CARTESIAN_POINT('',(20.,-5.,17.5));
#1480=DIRECTION('',(0.,0.,-1.));
#1481=DIRECTION('',(-1.,0.,0.));
#1482=AXIS2_PLACEMENT_3D('',#1479,#1480,#1481);
#1483=CYLINDRICAL_SURFACE('',#1482,5.);
#1484=ORIENTED_EDGE('',*,*,#1467,.F.);
#1485=CARTESIAN_POINT('',(20.,-5.,15.));
#1486=DIRECTION('',(0.,0.,-1.));
#1487=DIRECTION('',(-1.,0.,0.));
#1488=AXIS2_PLACEMENT_3D('',#1485,#1486,#1487);
#1489=CIRCLE('',#1488,5.);
#1490=CARTESIAN_POINT('',(25.,-4.99999999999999,15.));
#1491=VERTEX_POINT('',#1490);
#1492=EDGE_CURVE('E1567',#1491,#1458,#1489,.T.);
#1493=ORIENTED_EDGE('',*,*,#1492,.F.);
#1494=DIRECTION('',(0.,0.,-1.));
#1495=VECTOR('',#1494,1.);
#1496=CARTESIAN_POINT('',(25.,-4.99999999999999,17.5));
#1497=LINE('',#1496,#1495);
#1498=CARTESIAN_POINT('',(25.,-4.99999999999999,-15.));
#1499=VERTEX_POINT('',#1498);
#1500=EDGE_CURVE('E795',#1491,#1499,#1497,.T.);
#1501=ORIENTED_EDGE('',*,*,#1500,.T.);
#1502=CARTESIAN_POINT('',(20.,-5.,-15.));
#1503=DIRECTION('',(0.,0.,-1.));
#1504=DIRECTION('',(-1.,0.,0.));
#1505=AXIS2_PLACEMENT_3D('',#1502,#1503,#1504);
#1506=CIRCLE('',#1505,5.);
#1507=EDGE_CURVE('E1568',#1466,#1499,#1506,.F.);
#1508=ORIENTED_EDGE('',*,*,#1507,.F.);
#1509=EDGE_LOOP('',(#1484,#1493,#1501,#1508));
#1510=FACE_BOUND('',#1509,.T.);
#1511=ORIENTED_EDGE('',*,*,#1234,.T.);
#1512=EDGE_LOOP('',(#1511));
#1513=FACE_BOUND('',#1512,.T.);
#1514=ORIENTED_EDGE('',*,*,#1103,.T.);
#1515=EDGE_LOOP('',(#1514));
#1516=FACE_BOUND('',#1515,.T.);
#1517=ADVANCED_FACE('F1203',(#1510,#1513,#1516),#1483,.F.);
#1518=CARTESIAN_POINT('',(20.,-5.,-15.));
#1519=DIRECTION('',(0.,0.,-1.));
#1520=DIRECTION('',(-1.,0.,0.));
#1521=AXIS2_PLACEMENT_3D('',#1518,#1519,#1520);
#1522=DEGENERATE_TOROIDAL_SURFACE('',#1521,2.5,2.5,.T.);
#1523=CARTESIAN_POINT('',(22.5,-4.99999999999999,-15.));
#1524=DIRECTION('',(0.,-1.,0.));
#1525=DIRECTION('',(0.,0.,-1.));
#1526=AXIS2_PLACEMENT_3D('',#1523,#1524,#1525);
#1527=CIRCLE('',#1526,2.5);
#1528=CARTESIAN_POINT('',(22.5,-4.99999999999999,-17.5));
#1529=VERTEX_POINT('',#1528);
#1530=EDGE_CURVE('E778',#1529,#1499,#1527,.T.);
#1531=ORIENTED_EDGE('',*,*,#1530,.F.);
#1532=CARTESIAN_POINT('',(20.,-5.,-17.5));
#1533=DIRECTION('',(0.,0.,-1.));
#1534=DIRECTION('',(-1.,0.,0.));
#1535=AXIS2_PLACEMENT_3D('',#1532,#1533,#1534);
#1536=CIRCLE('',#1535,2.5);
#1537=CARTESIAN_POINT('',(18.0769230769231,-6.59742766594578,-17.5));
#1538=VERTEX_POINT('',#1537);
#1539=EDGE_CURVE('E697',#1529,#1538,#1536,.T.);
#1540=ORIENTED_EDGE('',*,*,#1539,.T.);
#1541=CARTESIAN_POINT('',(18.0769230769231,-6.59742766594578,-15.));
#1542=DIRECTION('',(-0.638971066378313,0.769230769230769,0.));
#1543=DIRECTION('',(-0.769230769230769,-0.638971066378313,0.));
#1544=AXIS2_PLACEMENT_3D('',#1541,#1542,#1543);
#1545=CIRCLE('',#1544,2.5);
#1546=EDGE_CURVE('E1577',#1538,#1466,#1545,.T.);
#1547=ORIENTED_EDGE('',*,*,#1546,.T.);
#1548=ORIENTED_EDGE('',*,*,#1507,.T.);
#1549=EDGE_LOOP('',(#1531,#1540,#1547,#1548));
#1550=FACE_BOUND('',#1549,.T.);
#1551=ADVANCED_FACE('F1211',(#1550),#1522,.F.);
#1552=CARTESIAN_POINT('',(15.,-9.15331193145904,-15.));
#1553=DIRECTION('',(0.,0.,-1.));
#1554=DIRECTION('',(-1.,0.,0.));
#1555=AXIS2_PLACEMENT_3D('',#1552,#1553,#1554);
#1556=TOROIDAL_SURFACE('',#1555,4.,2.5);
#1557=ORIENTED_EDGE('',*,*,#1546,.F.);
#1558=CARTESIAN_POINT('',(15.,-9.15331193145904,-17.5));
#1559=DIRECTION('',(0.,0.,-1.));
#1560=DIRECTION('',(-1.,0.,0.));
#1561=AXIS2_PLACEMENT_3D('',#1558,#1559,#1560);
#1562=CIRCLE('',#1561,4.);
#1563=CARTESIAN_POINT('',(11.9230769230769,-6.59742766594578,-17.5));
#1564=VERTEX_POINT('',#1563);
#1565=EDGE_CURVE('E1719',#1538,#1564,#1562,.F.);
#1566=ORIENTED_EDGE('',*,*,#1565,.T.);
#1567=CARTESIAN_POINT('',(11.9230769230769,-6.59742766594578,-15.));
#1568=DIRECTION('',(-0.638971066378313,-0.769230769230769,0.));
#1569=DIRECTION('',(0.769230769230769,-0.638971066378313,0.));
#1570=AXIS2_PLACEMENT_3D('',#1567,#1568,#1569);
#1571=CIRCLE('',#1570,2.5);
#1572=EDGE_CURVE('E1722',#1564,#1433,#1571,.T.);
#1573=ORIENTED_EDGE('',*,*,#1572,.T.);
#1574=ORIENTED_EDGE('',*,*,#1474,.T.);
#1575=EDGE_LOOP('',(#1557,#1566,#1573,#1574));
#1576=FACE_BOUND('',#1575,.T.);
#1577=ADVANCED_FACE('F1219',(#1576),#1556,.F.);
#1578=CARTESIAN_POINT('',(10.,-5.,-15.));
#1579=DIRECTION('',(0.,0.,-1.));
#1580=DIRECTION('',(-1.,0.,0.));
#1581=AXIS2_PLACEMENT_3D('',#1578,#1579,#1580);
#1582=DEGENERATE_TOROIDAL_SURFACE('',#1581,2.5,2.5,.T.);
#1583=ORIENTED_EDGE('',*,*,#1572,.F.);
#1584=CARTESIAN_POINT('',(10.,-5.,-17.5));
#1585=DIRECTION('',(0.,0.,-1.));
#1586=DIRECTION('',(-1.,0.,0.));
#1587=AXIS2_PLACEMENT_3D('',#1584,#1585,#1586);
#1588=CIRCLE('',#1587,2.5);
#1589=CARTESIAN_POINT('',(8.07692307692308,-6.59742766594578,-17.5));
#1590=VERTEX_POINT('',#1589);
#1591=EDGE_CURVE('E1714',#1564,#1590,#1588,.T.);
#1592=ORIENTED_EDGE('',*,*,#1591,.T.);
#1593=CARTESIAN_POINT('',(8.07692307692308,-6.59742766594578,-15.));
#1594=DIRECTION('',(-0.638971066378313,0.769230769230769,0.));
#1595=DIRECTION('',(-0.769230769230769,-0.638971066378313,0.));
#1596=AXIS2_PLACEMENT_3D('',#1593,#1594,#1595);
#1597=CIRCLE('',#1596,2.5);
#1598=EDGE_CURVE('E1717',#1590,#1400,#1597,.T.);
#1599=ORIENTED_EDGE('',*,*,#1598,.T.);
#1600=ORIENTED_EDGE('',*,*,#1441,.T.);
#1601=EDGE_LOOP('',(#1583,#1592,#1599,#1600));
#1602=FACE_BOUND('',#1601,.T.);
#1603=ADVANCED_FACE('F1227',(#1602),#1582,.F.);
#1604=CARTESIAN_POINT('',(5.,-9.15331193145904,-15.));
#1605=DIRECTION('',(0.,0.,-1.));
#1606=DIRECTION('',(-1.,0.,0.));
#1607=AXIS2_PLACEMENT_3D('',#1604,#1605,#1606);
#1608=TOROIDAL_SURFACE('',#1607,4.,2.5);
#1609=ORIENTED_EDGE('',*,*,#1598,.F.);
#1610=CARTESIAN_POINT('',(5.,-9.15331193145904,-17.5));
#1611=DIRECTION('',(0.,0.,-1.));
#1612=DIRECTION('',(-1.,0.,0.));
#1613=AXIS2_PLACEMENT_3D('',#1610,#1611,#1612);
#1614=CIRCLE('',#1613,4.);
#1615=CARTESIAN_POINT('',(1.92307692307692,-6.59742766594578,-17.5));
#1616=VERTEX_POINT('',#1615);
#1617=EDGE_CURVE('E1713',#1590,#1616,#1614,.F.);
#1618=ORIENTED_EDGE('',*,*,#1617,.T.);
#1619=CARTESIAN_POINT('',(1.92307692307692,-6.59742766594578,-15.));
#1620=DIRECTION('',(-0.638971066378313,-0.769230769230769,0.));
#1621=DIRECTION('',(0.769230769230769,-0.638971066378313,0.));
#1622=AXIS2_PLACEMENT_3D('',#1619,#1620,#1621);
#1623=CIRCLE('',#1622,2.5);
#1624=EDGE_CURVE('E1711',#1616,#1367,#1623,.T.);
#1625=ORIENTED_EDGE('',*,*,#1624,.T.);
#1626=ORIENTED_EDGE('',*,*,#1408,.T.);
#1627=EDGE_LOOP('',(#1609,#1618,#1625,#1626));
#1628=FACE_BOUND('',#1627,.T.);
#1629=ADVANCED_FACE('F1235',(#1628),#1608,.F.);
#1630=CARTESIAN_POINT('',(0.,-5.,-15.));
#1631=DIRECTION('',(0.,0.,-1.));
#1632=DIRECTION('',(-1.,0.,0.));
#1633=AXIS2_PLACEMENT_3D('',#1630,#1631,#1632);
#1634=DEGENERATE_TOROIDAL_SURFACE('',#1633,2.5,2.5,.T.);
#1635=ORIENTED_EDGE('',*,*,#1624,.F.);
#1636=CARTESIAN_POINT('',(0.,-5.,-17.5));
#1637=DIRECTION('',(0.,0.,-1.));
#1638=DIRECTION('',(-1.,0.,0.));
#1639=AXIS2_PLACEMENT_3D('',#1636,#1637,#1638);
#1640=CIRCLE('',#1639,2.5);
#1641=CARTESIAN_POINT('',(-1.92307692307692,-6.59742766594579,-17.5));
#1642=VERTEX_POINT('',#1641);
#1643=EDGE_CURVE('E1754',#1616,#1642,#1640,.T.);
#1644=ORIENTED_EDGE('',*,*,#1643,.T.);
#1645=CARTESIAN_POINT('',(-1.92307692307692,-6.59742766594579,-15.));
#1646=DIRECTION('',(-0.638971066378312,0.76923076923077,0.));
#1647=DIRECTION('',(-0.76923076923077,-0.638971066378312,0.));
#1648=AXIS2_PLACEMENT_3D('',#1645,#1646,#1647);
#1649=CIRCLE('',#1648,2.5);
#1650=EDGE_CURVE('E1710',#1642,#1334,#1649,.T.);
#1651=ORIENTED_EDGE('',*,*,#1650,.T.);
#1652=ORIENTED_EDGE('',*,*,#1375,.T.);
#1653=EDGE_LOOP('',(#1635,#1644,#1651,#1652));
#1654=FACE_BOUND('',#1653,.T.);
#1655=ADVANCED_FACE('F1243',(#1654),#1634,.F.);
#1656=CARTESIAN_POINT('',(-5.,-9.15331193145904,-15.));
#1657=DIRECTION('',(0.,0.,-1.));
#1658=DIRECTION('',(-1.,0.,0.));
#1659=AXIS2_PLACEMENT_3D('',#1656,#1657,#1658);
#1660=TOROIDAL_SURFACE('',#1659,4.,2.5);
#1661=ORIENTED_EDGE('',*,*,#1650,.F.);
#1662=CARTESIAN_POINT('',(-5.,-9.15331193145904,-17.5));
#1663=DIRECTION('',(0.,0.,-1.));
#1664=DIRECTION('',(-1.,0.,0.));
#1665=AXIS2_PLACEMENT_3D('',#1662,#1663,#1664);
#1666=CIRCLE('',#1665,4.);
#1667=CARTESIAN_POINT('',(-8.07692307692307,-6.59742766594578,-17.5));
#1668=VERTEX_POINT('',#1667);
#1669=EDGE_CURVE('E1749',#1642,#1668,#1666,.F.);
#1670=ORIENTED_EDGE('',*,*,#1669,.T.);
#1671=CARTESIAN_POINT('',(-8.07692307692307,-6.59742766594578,-15.));
#1672=DIRECTION('',(-0.638971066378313,-0.769230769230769,0.));
#1673=DIRECTION('',(0.769230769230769,-0.638971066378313,0.));
#1674=AXIS2_PLACEMENT_3D('',#1671,#1672,#1673);
#1675=CIRCLE('',#1674,2.5);
#1676=EDGE_CURVE('E1745',#1668,#1301,#1675,.T.);
#1677=ORIENTED_EDGE('',*,*,#1676,.T.);
#1678=ORIENTED_EDGE('',*,*,#1342,.T.);
#1679=EDGE_LOOP('',(#1661,#1670,#1677,#1678));
#1680=FACE_BOUND('',#1679,.T.);
#1681=ADVANCED_FACE('F1251',(#1680),#1660,.F.);
#1682=CARTESIAN_POINT('',(-10.,-5.,-15.));
#1683=DIRECTION('',(0.,0.,-1.));
#1684=DIRECTION('',(-1.,0.,0.));
#1685=AXIS2_PLACEMENT_3D('',#1682,#1683,#1684);
#1686=DEGENERATE_TOROIDAL_SURFACE('',#1685,2.5,2.5,.T.);
#1687=ORIENTED_EDGE('',*,*,#1676,.F.);
#1688=CARTESIAN_POINT('',(-10.,-5.,-17.5));
#1689=DIRECTION('',(0.,0.,-1.));
#1690=DIRECTION('',(-1.,0.,0.));
#1691=AXIS2_PLACEMENT_3D('',#1688,#1689,#1690);
#1692=CIRCLE('',#1691,2.5);
#1693=CARTESIAN_POINT('',(-11.9230769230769,-6.59742766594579,-17.5));
#1694=VERTEX_POINT('',#1693);
#1695=EDGE_CURVE('E1747',#1668,#1694,#1692,.T.);
#1696=ORIENTED_EDGE('',*,*,#1695,.T.);
#1697=CARTESIAN_POINT('',(-11.9230769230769,-6.59742766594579,-15.));
#1698=DIRECTION('',(-0.638971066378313,0.76923076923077,0.));
#1699=DIRECTION('',(-0.76923076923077,-0.638971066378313,0.));
#1700=AXIS2_PLACEMENT_3D('',#1697,#1698,#1699);
#1701=CIRCLE('',#1700,2.5);
#1702=EDGE_CURVE('E1743',#1694,#1268,#1701,.T.);
#1703=ORIENTED_EDGE('',*,*,#1702,.T.);
#1704=ORIENTED_EDGE('',*,*,#1309,.T.);
#1705=EDGE_LOOP('',(#1687,#1696,#1703,#1704));
#1706=FACE_BOUND('',#1705,.T.);
#1707=ADVANCED_FACE('F1259',(#1706),#1686,.F.);
#1708=CARTESIAN_POINT('',(-15.,-9.15331193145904,-15.));
#1709=DIRECTION('',(0.,0.,-1.));
#1710=DIRECTION('',(-1.,0.,0.));
#1711=AXIS2_PLACEMENT_3D('',#1708,#1709,#1710);
#1712=TOROIDAL_SURFACE('',#1711,4.,2.5);
#1713=ORIENTED_EDGE('',*,*,#1702,.F.);
#1714=CARTESIAN_POINT('',(-15.,-9.15331193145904,-17.5));
#1715=DIRECTION('',(0.,0.,-1.));
#1716=DIRECTION('',(-1.,0.,0.));
#1717=AXIS2_PLACEMENT_3D('',#1714,#1715,#1716);
#1718=CIRCLE('',#1717,4.);
#1719=CARTESIAN_POINT('',(-18.0769230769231,-6.59742766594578,-17.5));
#1720=VERTEX_POINT('',#1719);
#1721=EDGE_CURVE('E915',#1694,#1720,#1718,.F.);
#1722=ORIENTED_EDGE('',*,*,#1721,.T.);
#1723=CARTESIAN_POINT('',(-18.0769230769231,-6.59742766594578,-15.));
#1724=DIRECTION('',(-0.638971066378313,-0.769230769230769,0.));
#1725=DIRECTION('',(0.769230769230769,-0.638971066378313,0.));
#1726=AXIS2_PLACEMENT_3D('',#1723,#1724,#1725);
#1727=CIRCLE('',#1726,2.5);
#1728=EDGE_CURVE('E917',#1720,#1251,#1727,.T.);
#1729=ORIENTED_EDGE('',*,*,#1728,.T.);
#1730=ORIENTED_EDGE('',*,*,#1276,.T.);
#1731=EDGE_LOOP('',(#1713,#1722,#1729,#1730));
#1732=FACE_BOUND('',#1731,.T.);
#1733=ADVANCED_FACE('F1267',(#1732),#1712,.F.);
#1734=CARTESIAN_POINT('',(-20.,-5.,-15.));
#1735=DIRECTION('',(0.,0.,-1.));
#1736=DIRECTION('',(-1.,0.,0.));
#1737=AXIS2_PLACEMENT_3D('',#1734,#1735,#1736);
#1738=DEGENERATE_TOROIDAL_SURFACE('',#1737,2.5,2.5,.T.);
#1739=ORIENTED_EDGE('',*,*,#1728,.F.);
#1740=CARTESIAN_POINT('',(-20.,-5.,-17.5));
#1741=DIRECTION('',(0.,0.,-1.));
#1742=DIRECTION('',(-1.,0.,0.));
#1743=AXIS2_PLACEMENT_3D('',#1740,#1741,#1742);
#1744=CIRCLE('',#1743,2.5);
#1745=CARTESIAN_POINT('',(-22.5,-5.,-17.5));
#1746=VERTEX_POINT('',#1745);
#1747=EDGE_CURVE('E903',#1720,#1746,#1744,.T.);
#1748=ORIENTED_EDGE('',*,*,#1747,.T.);
#1749=CARTESIAN_POINT('',(-22.5,-5.,-15.));
#1750=DIRECTION('',(0.,1.,0.));
#1751=DIRECTION('',(0.,0.,1.));
#1752=AXIS2_PLACEMENT_3D('',#1749,#1750,#1751);
#1753=CIRCLE('',#1752,2.5);
#1754=CARTESIAN_POINT('',(-25.,-5.,-15.));
#1755=VERTEX_POINT('',#1754);
#1756=EDGE_CURVE('E696',#1746,#1755,#1753,.T.);
#1757=ORIENTED_EDGE('',*,*,#1756,.T.);
#1758=CARTESIAN_POINT('',(-20.,-5.,-15.));
#1759=DIRECTION('',(0.,0.,-1.));
#1760=DIRECTION('',(-1.,0.,0.));
#1761=AXIS2_PLACEMENT_3D('',#1758,#1759,#1760);
#1762=CIRCLE('',#1761,5.);
#1763=EDGE_CURVE('E908',#1755,#1251,#1762,.F.);
#1764=ORIENTED_EDGE('',*,*,#1763,.T.);
#1765=EDGE_LOOP('',(#1739,#1748,#1757,#1764));
#1766=FACE_BOUND('',#1765,.T.);
#1767=ADVANCED_FACE('F907',(#1766),#1738,.F.);
#1768=CARTESIAN_POINT('',(-20.,-5.,17.5));
#1769=DIRECTION('',(0.,0.,-1.));
#1770=DIRECTION('',(-1.,0.,0.));
#1771=AXIS2_PLACEMENT_3D('',#1768,#1769,#1770);
#1772=CYLINDRICAL_SURFACE('',#1771,5.);
#1773=DIRECTION('',(0.,0.,-1.));
#1774=VECTOR('',#1773,1.);
#1775=CARTESIAN_POINT('',(-25.,-5.,17.5));
#1776=LINE('',#1775,#1774);
#1777=CARTESIAN_POINT('',(-25.,-5.,15.));
#1778=VERTEX_POINT('',#1777);
#1779=EDGE_CURVE('E662',#1778,#1755,#1776,.T.);
#1780=ORIENTED_EDGE('',*,*,#1779,.F.);
#1781=CARTESIAN_POINT('',(-20.,-5.,15.));
#1782=DIRECTION('',(0.,0.,-1.));
#1783=DIRECTION('',(-1.,0.,0.));
#1784=AXIS2_PLACEMENT_3D('',#1781,#1782,#1783);
#1785=CIRCLE('',#1784,5.);
#1786=EDGE_CURVE('E902',#1249,#1778,#1785,.T.);
#1787=ORIENTED_EDGE('',*,*,#1786,.F.);
#1788=ORIENTED_EDGE('',*,*,#1252,.T.);
#1789=ORIENTED_EDGE('',*,*,#1763,.F.);
#1790=EDGE_LOOP('',(#1780,#1787,#1788,#1789));
#1791=FACE_BOUND('',#1790,.T.);
#1792=ORIENTED_EDGE('',*,*,#972,.T.);
#1793=EDGE_LOOP('',(#1792));
#1794=FACE_BOUND('',#1793,.T.);
#1795=ORIENTED_EDGE('',*,*,#841,.T.);
#1796=EDGE_LOOP('',(#1795));
#1797=FACE_BOUND('',#1796,.T.);
#1798=ADVANCED_FACE('F910',(#1791,#1794,#1797),#1772,.F.);
#1799=CARTESIAN_POINT('',(-20.,-5.,15.));
#1800=DIRECTION('',(0.,0.,-1.));
#1801=DIRECTION('',(-1.,0.,0.));
#1802=AXIS2_PLACEMENT_3D('',#1799,#1800,#1801);
#1803=DEGENERATE_TOROIDAL_SURFACE('',#1802,2.5,2.5,.T.);
#1804=CARTESIAN_POINT('',(-18.0769230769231,-6.59742766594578,15.));
#1805=DIRECTION('',(-0.638971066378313,-0.769230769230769,0.));
#1806=DIRECTION('',(0.769230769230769,-0.638971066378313,0.));
#1807=AXIS2_PLACEMENT_3D('',#1804,#1805,#1806);
#1808=CIRCLE('',#1807,2.5);
#1809=CARTESIAN_POINT('',(-18.0769230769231,-6.59742766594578,17.5));
#1810=VERTEX_POINT('',#1809);
#1811=EDGE_CURVE('E1627',#1249,#1810,#1808,.T.);
#1812=ORIENTED_EDGE('',*,*,#1811,.F.);
#1813=ORIENTED_EDGE('',*,*,#1786,.T.);
#1814=CARTESIAN_POINT('',(-22.5,-5.,15.));
#1815=DIRECTION('',(0.,1.,0.));
#1816=DIRECTION('',(0.,0.,1.));
#1817=AXIS2_PLACEMENT_3D('',#1814,#1815,#1816);
#1818=CIRCLE('',#1817,2.5);
#1819=CARTESIAN_POINT('',(-22.5,-5.,17.5));
#1820=VERTEX_POINT('',#1819);
#1821=EDGE_CURVE('E660',#1778,#1820,#1818,.T.);
#1822=ORIENTED_EDGE('',*,*,#1821,.T.);
#1823=CARTESIAN_POINT('',(-20.,-5.,17.5));
#1824=DIRECTION('',(0.,0.,-1.));
#1825=DIRECTION('',(-1.,0.,0.));
#1826=AXIS2_PLACEMENT_3D('',#1823,#1824,#1825);
#1827=CIRCLE('',#1826,2.5);
#1828=EDGE_CURVE('E617',#1820,#1810,#1827,.F.);
#1829=ORIENTED_EDGE('',*,*,#1828,.T.);
#1830=EDGE_LOOP('',(#1812,#1813,#1822,#1829));
#1831=FACE_BOUND('',#1830,.T.);
#1832=ADVANCED_FACE('F1287',(#1831),#1803,.F.);
#1833=CARTESIAN_POINT('',(-15.,-9.15331193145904,15.));
#1834=DIRECTION('',(0.,0.,-1.));
#1835=DIRECTION('',(-1.,0.,0.));
#1836=AXIS2_PLACEMENT_3D('',#1833,#1834,#1835);
#1837=TOROIDAL_SURFACE('',#1836,4.,2.5);
#1838=CARTESIAN_POINT('',(-11.9230769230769,-6.59742766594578,15.));
#1839=DIRECTION('',(-0.638971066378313,0.769230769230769,0.));
#1840=DIRECTION('',(-0.769230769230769,-0.638971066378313,0.));
#1841=AXIS2_PLACEMENT_3D('',#1838,#1839,#1840);
#1842=CIRCLE('',#1841,2.5);
#1843=CARTESIAN_POINT('',(-11.9230769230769,-6.59742766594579,17.5));
#1844=VERTEX_POINT('',#1843);
#1845=EDGE_CURVE('E1619',#1260,#1844,#1842,.T.);
#1846=ORIENTED_EDGE('',*,*,#1845,.F.);
#1847=ORIENTED_EDGE('',*,*,#1261,.T.);
#1848=ORIENTED_EDGE('',*,*,#1811,.T.);
#1849=CARTESIAN_POINT('',(-15.,-9.15331193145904,17.5));
#1850=DIRECTION('',(0.,0.,-1.));
#1851=DIRECTION('',(-1.,0.,0.));
#1852=AXIS2_PLACEMENT_3D('',#1849,#1850,#1851);
#1853=CIRCLE('',#1852,4.);
#1854=EDGE_CURVE('E1613',#1810,#1844,#1853,.T.);
#1855=ORIENTED_EDGE('',*,*,#1854,.T.);
#1856=EDGE_LOOP('',(#1846,#1847,#1848,#1855));
#1857=FACE_BOUND('',#1856,.T.);
#1858=ADVANCED_FACE('F1293',(#1857),#1837,.F.);
#1859=CARTESIAN_POINT('',(-10.,-5.,15.));
#1860=DIRECTION('',(0.,0.,-1.));
#1861=DIRECTION('',(-1.,0.,0.));
#1862=AXIS2_PLACEMENT_3D('',#1859,#1860,#1861);
#1863=DEGENERATE_TOROIDAL_SURFACE('',#1862,2.5,2.5,.T.);
#1864=CARTESIAN_POINT('',(-8.07692307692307,-6.59742766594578,15.));
#1865=DIRECTION('',(-0.638971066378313,-0.769230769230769,0.));
#1866=DIRECTION('',(0.769230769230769,-0.638971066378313,0.));
#1867=AXIS2_PLACEMENT_3D('',#1864,#1865,#1866);
#1868=CIRCLE('',#1867,2.5);
#1869=CARTESIAN_POINT('',(-8.07692307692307,-6.59742766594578,17.5));
#1870=VERTEX_POINT('',#1869);
#1871=EDGE_CURVE('E1610',#1293,#1870,#1868,.T.);
#1872=ORIENTED_EDGE('',*,*,#1871,.F.);
#1873=ORIENTED_EDGE('',*,*,#1294,.T.);
#1874=ORIENTED_EDGE('',*,*,#1845,.T.);
#1875=CARTESIAN_POINT('',(-10.,-5.,17.5));
#1876=DIRECTION('',(0.,0.,-1.));
#1877=DIRECTION('',(-1.,0.,0.));
#1878=AXIS2_PLACEMENT_3D('',#1875,#1876,#1877);
#1879=CIRCLE('',#1878,2.5);
#1880=EDGE_CURVE('E1604',#1844,#1870,#1879,.F.);
#1881=ORIENTED_EDGE('',*,*,#1880,.T.);
#1882=EDGE_LOOP('',(#1872,#1873,#1874,#1881));
#1883=FACE_BOUND('',#1882,.T.);
#1884=ADVANCED_FACE('F1300',(#1883),#1863,.F.);
#1885=CARTESIAN_POINT('',(-5.,-9.15331193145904,15.));
#1886=DIRECTION('',(0.,0.,-1.));
#1887=DIRECTION('',(-1.,0.,0.));
#1888=AXIS2_PLACEMENT_3D('',#1885,#1886,#1887);
#1889=TOROIDAL_SURFACE('',#1888,4.,2.5);
#1890=CARTESIAN_POINT('',(-1.92307692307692,-6.59742766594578,15.));
#1891=DIRECTION('',(-0.638971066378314,0.769230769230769,0.));
#1892=DIRECTION('',(-0.769230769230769,-0.638971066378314,0.));
#1893=AXIS2_PLACEMENT_3D('',#1890,#1891,#1892);
#1894=CIRCLE('',#1893,2.5);
#1895=CARTESIAN_POINT('',(-1.92307692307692,-6.59742766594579,17.5));
#1896=VERTEX_POINT('',#1895);
#1897=EDGE_CURVE('E1602',#1326,#1896,#1894,.T.);
#1898=ORIENTED_EDGE('',*,*,#1897,.F.);
#1899=ORIENTED_EDGE('',*,*,#1327,.T.);
#1900=ORIENTED_EDGE('',*,*,#1871,.T.);
#1901=CARTESIAN_POINT('',(-5.,-9.15331193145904,17.5));
#1902=DIRECTION('',(0.,0.,-1.));
#1903=DIRECTION('',(-1.,0.,0.));
#1904=AXIS2_PLACEMENT_3D('',#1901,#1902,#1903);
#1905=CIRCLE('',#1904,4.);
#1906=EDGE_CURVE('E1596',#1870,#1896,#1905,.T.);
#1907=ORIENTED_EDGE('',*,*,#1906,.T.);
#1908=EDGE_LOOP('',(#1898,#1899,#1900,#1907));
#1909=FACE_BOUND('',#1908,.T.);
#1910=ADVANCED_FACE('F1308',(#1909),#1889,.F.);
#1911=CARTESIAN_POINT('',(0.,-5.,15.));
#1912=DIRECTION('',(0.,0.,-1.));
#1913=DIRECTION('',(-1.,0.,0.));
#1914=AXIS2_PLACEMENT_3D('',#1911,#1912,#1913);
#1915=DEGENERATE_TOROIDAL_SURFACE('',#1914,2.5,2.5,.T.);
#1916=CARTESIAN_POINT('',(1.92307692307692,-6.59742766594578,15.));
#1917=DIRECTION('',(-0.638971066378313,-0.769230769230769,0.));
#1918=DIRECTION('',(0.769230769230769,-0.638971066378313,0.));
#1919=AXIS2_PLACEMENT_3D('',#1916,#1917,#1918);
#1920=CIRCLE('',#1919,2.5);
#1921=CARTESIAN_POINT('',(1.92307692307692,-6.59742766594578,17.5));
#1922=VERTEX_POINT('',#1921);
#1923=EDGE_CURVE('E1594',#1359,#1922,#1920,.T.);
#1924=ORIENTED_EDGE('',*,*,#1923,.F.);
#1925=ORIENTED_EDGE('',*,*,#1360,.T.);
#1926=ORIENTED_EDGE('',*,*,#1897,.T.);
#1927=CARTESIAN_POINT('',(0.,-5.,17.5));
#1928=DIRECTION('',(0.,0.,-1.));
#1929=DIRECTION('',(-1.,0.,0.));
#1930=AXIS2_PLACEMENT_3D('',#1927,#1928,#1929);
#1931=CIRCLE('',#1930,2.5);
#1932=EDGE_CURVE('E232',#1896,#1922,#1931,.F.);
#1933=ORIENTED_EDGE('',*,*,#1932,.T.);
#1934=EDGE_LOOP('',(#1924,#1925,#1926,#1933));
#1935=FACE_BOUND('',#1934,.T.);
#1936=ADVANCED_FACE('F1316',(#1935),#1915,.F.);
#1937=CARTESIAN_POINT('',(5.,-9.15331193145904,15.));
#1938=DIRECTION('',(0.,0.,-1.));
#1939=DIRECTION('',(-1.,0.,0.));
#1940=AXIS2_PLACEMENT_3D('',#1937,#1938,#1939);
#1941=TOROIDAL_SURFACE('',#1940,4.,2.5);
#1942=CARTESIAN_POINT('',(8.07692307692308,-6.59742766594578,15.));
#1943=DIRECTION('',(-0.638971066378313,0.769230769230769,0.));
#1944=DIRECTION('',(-0.769230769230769,-0.638971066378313,0.));
#1945=AXIS2_PLACEMENT_3D('',#1942,#1943,#1944);
#1946=CIRCLE('',#1945,2.5);
#1947=CARTESIAN_POINT('',(8.07692307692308,-6.59742766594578,17.5));
#1948=VERTEX_POINT('',#1947);
#1949=EDGE_CURVE('E1587',#1392,#1948,#1946,.T.);
#1950=ORIENTED_EDGE('',*,*,#1949,.F.);
#1951=ORIENTED_EDGE('',*,*,#1393,.T.);
#1952=ORIENTED_EDGE('',*,*,#1923,.T.);
#1953=CARTESIAN_POINT('',(5.,-9.15331193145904,17.5));
#1954=DIRECTION('',(0.,0.,-1.));
#1955=DIRECTION('',(-1.,0.,0.));
#1956=AXIS2_PLACEMENT_3D('',#1953,#1954,#1955);
#1957=CIRCLE('',#1956,4.);
#1958=EDGE_CURVE('E238',#1922,#1948,#1957,.T.);
#1959=ORIENTED_EDGE('',*,*,#1958,.T.);
#1960=EDGE_LOOP('',(#1950,#1951,#1952,#1959));
#1961=FACE_BOUND('',#1960,.T.);
#1962=ADVANCED_FACE('F1324',(#1961),#1941,.F.);
#1963=CARTESIAN_POINT('',(10.,-5.,15.));
#1964=DIRECTION('',(0.,0.,-1.));
#1965=DIRECTION('',(-1.,0.,0.));
#1966=AXIS2_PLACEMENT_3D('',#1963,#1964,#1965);
#1967=DEGENERATE_TOROIDAL_SURFACE('',#1966,2.5,2.5,.T.);
#1968=CARTESIAN_POINT('',(11.9230769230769,-6.59742766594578,15.));
#1969=DIRECTION('',(-0.638971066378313,-0.769230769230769,0.));
#1970=DIRECTION('',(0.769230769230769,-0.638971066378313,0.));
#1971=AXIS2_PLACEMENT_3D('',#1968,#1969,#1970);
#1972=CIRCLE('',#1971,2.5);
#1973=CARTESIAN_POINT('',(11.9230769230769,-6.59742766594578,17.5));
#1974=VERTEX_POINT('',#1973);
#1975=EDGE_CURVE('E1581',#1425,#1974,#1972,.T.);
#1976=ORIENTED_EDGE('',*,*,#1975,.F.);
#1977=ORIENTED_EDGE('',*,*,#1426,.T.);
#1978=ORIENTED_EDGE('',*,*,#1949,.T.);
#1979=CARTESIAN_POINT('',(10.,-5.,17.5));
#1980=DIRECTION('',(0.,0.,-1.));
#1981=DIRECTION('',(-1.,0.,0.));
#1982=AXIS2_PLACEMENT_3D('',#1979,#1980,#1981);
#1983=CIRCLE('',#1982,2.5);
#1984=EDGE_CURVE('E245',#1948,#1974,#1983,.F.);
#1985=ORIENTED_EDGE('',*,*,#1984,.T.);
#1986=EDGE_LOOP('',(#1976,#1977,#1978,#1985));
#1987=FACE_BOUND('',#1986,.T.);
#1988=ADVANCED_FACE('F1331',(#1987),#1967,.F.);
#1989=CARTESIAN_POINT('',(15.,-9.15331193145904,15.));
#1990=DIRECTION('',(0.,0.,-1.));
#1991=DIRECTION('',(-1.,0.,0.));
#1992=AXIS2_PLACEMENT_3D('',#1989,#1990,#1991);
#1993=TOROIDAL_SURFACE('',#1992,4.,2.5);
#1994=CARTESIAN_POINT('',(18.0769230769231,-6.59742766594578,15.));
#1995=DIRECTION('',(-0.638971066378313,0.769230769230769,0.));
#1996=DIRECTION('',(-0.769230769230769,-0.638971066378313,0.));
#1997=AXIS2_PLACEMENT_3D('',#1994,#1995,#1996);
#1998=CIRCLE('',#1997,2.5);
#1999=CARTESIAN_POINT('',(18.0769230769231,-6.59742766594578,17.5));
#2000=VERTEX_POINT('',#1999);
#2001=EDGE_CURVE('E1580',#1458,#2000,#1998,.T.);
#2002=ORIENTED_EDGE('',*,*,#2001,.F.);
#2003=ORIENTED_EDGE('',*,*,#1459,.T.);
#2004=ORIENTED_EDGE('',*,*,#1975,.T.);
#2005=CARTESIAN_POINT('',(15.,-9.15331193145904,17.5));
#2006=DIRECTION('',(0.,0.,-1.));
#2007=DIRECTION('',(-1.,0.,0.));
#2008=AXIS2_PLACEMENT_3D('',#2005,#2006,#2007);
#2009=CIRCLE('',#2008,4.);
#2010=EDGE_CURVE('E1571',#1974,#2000,#2009,.T.);
#2011=ORIENTED_EDGE('',*,*,#2010,.T.);
#2012=EDGE_LOOP('',(#2002,#2003,#2004,#2011));
#2013=FACE_BOUND('',#2012,.T.);
#2014=ADVANCED_FACE('F1338',(#2013),#1993,.F.);
#2015=CARTESIAN_POINT('',(20.,-5.,15.));
#2016=DIRECTION('',(0.,0.,-1.));
#2017=DIRECTION('',(-1.,0.,0.));
#2018=AXIS2_PLACEMENT_3D('',#2015,#2016,#2017);
#2019=DEGENERATE_TOROIDAL_SURFACE('',#2018,2.5,2.5,.T.);
#2020=CARTESIAN_POINT('',(22.5,-4.99999999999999,15.));
#2021=DIRECTION('',(0.,-1.,0.));
#2022=DIRECTION('',(0.,0.,-1.));
#2023=AXIS2_PLACEMENT_3D('',#2020,#2021,#2022);
#2024=CIRCLE('',#2023,2.5);
#2025=CARTESIAN_POINT('',(22.5,-4.99999999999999,17.5));
#2026=VERTEX_POINT('',#2025);
#2027=EDGE_CURVE('E1561',#1491,#2026,#2024,.T.);
#2028=ORIENTED_EDGE('',*,*,#2027,.F.);
#2029=ORIENTED_EDGE('',*,*,#1492,.T.);
#2030=ORIENTED_EDGE('',*,*,#2001,.T.);
#2031=CARTESIAN_POINT('',(20.,-5.,17.5));
#2032=DIRECTION('',(0.,0.,-1.));
#2033=DIRECTION('',(-1.,0.,0.));
#2034=AXIS2_PLACEMENT_3D('',#2031,#2032,#2033);
#2035=CIRCLE('',#2034,2.5);
#2036=EDGE_CURVE('E177',#2000,#2026,#2035,.F.);
#2037=ORIENTED_EDGE('',*,*,#2036,.T.);
#2038=EDGE_LOOP('',(#2028,#2029,#2030,#2037));
#2039=FACE_BOUND('',#2038,.T.);
#2040=ADVANCED_FACE('F1345',(#2039),#2019,.F.);
#2041=CARTESIAN_POINT('',(22.5,-5.,15.));
#2042=DIRECTION('',(0.,1.,0.));
#2043=DIRECTION('',(0.,0.,1.));
#2044=AXIS2_PLACEMENT_3D('',#2041,#2042,#2043);
#2045=CYLINDRICAL_SURFACE('',#2044,2.5);
#2046=ORIENTED_EDGE('',*,*,#572,.T.);
#2047=DIRECTION('',(0.,1.,0.));
#2048=VECTOR('',#2047,1.);
#2049=CARTESIAN_POINT('',(25.,0.,15.));
#2050=LINE('',#2049,#2048);
#2051=EDGE_CURVE('E782',#562,#1491,#2050,.F.);
#2052=ORIENTED_EDGE('',*,*,#2051,.T.);
#2053=ORIENTED_EDGE('',*,*,#2027,.T.);
#2054=DIRECTION('',(0.,1.,0.));
#2055=VECTOR('',#2054,1.);
#2056=CARTESIAN_POINT('',(22.5,-5.,17.5));
#2057=LINE('',#2056,#2055);
#2058=EDGE_CURVE('E613',#2026,#571,#2057,.T.);
#2059=ORIENTED_EDGE('',*,*,#2058,.T.);
#2060=EDGE_LOOP('',(#2046,#2052,#2053,#2059));
#2061=FACE_BOUND('',#2060,.T.);
#2062=ADVANCED_FACE('F1353',(#2061),#2045,.F.);
#2063=CARTESIAN_POINT('',(25.,0.,17.5));
#2064=DIRECTION('',(-1.,0.,0.));
#2065=DIRECTION('',(0.,0.,1.));
#2066=AXIS2_PLACEMENT_3D('',#2063,#2064,#2065);
#2067=PLANE('',#2066);
#2068=ORIENTED_EDGE('',*,*,#658,.T.);
#2069=DIRECTION('',(0.,1.,0.));
#2070=VECTOR('',#2069,1.);
#2071=CARTESIAN_POINT('',(25.,0.,-15.));
#2072=LINE('',#2071,#2070);
#2073=EDGE_CURVE('E683',#1499,#655,#2072,.T.);
#2074=ORIENTED_EDGE('',*,*,#2073,.F.);
#2075=ORIENTED_EDGE('',*,*,#1500,.F.);
#2076=ORIENTED_EDGE('',*,*,#2051,.F.);
#2077=ORIENTED_EDGE('',*,*,#563,.T.);
#2078=ORIENTED_EDGE('',*,*,#539,.T.);
#2079=ORIENTED_EDGE('',*,*,#515,.T.);
#2080=ORIENTED_EDGE('',*,*,#492,.T.);
#2081=EDGE_LOOP('',(#2068,#2074,#2075,#2076,#2077,#2078,#2079,#2080));
#2082=FACE_BOUND('',#2081,.T.);
#2083=ADVANCED_FACE('F813',(#2082),#2067,.T.);
#2084=CARTESIAN_POINT('',(22.5,0.,-15.));
#2085=DIRECTION('',(0.,-1.,0.));
#2086=DIRECTION('',(0.,0.,-1.));
#2087=AXIS2_PLACEMENT_3D('',#2084,#2085,#2086);
#2088=CYLINDRICAL_SURFACE('',#2087,2.5);
#2089=ORIENTED_EDGE('',*,*,#656,.T.);
#2090=DIRECTION('',(0.,1.,0.));
#2091=VECTOR('',#2090,1.);
#2092=CARTESIAN_POINT('',(22.5,-4.99999999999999,-17.5));
#2093=LINE('',#2092,#2091);
#2094=EDGE_CURVE('E682',#646,#1529,#2093,.F.);
#2095=ORIENTED_EDGE('',*,*,#2094,.T.);
#2096=ORIENTED_EDGE('',*,*,#1530,.T.);
#2097=ORIENTED_EDGE('',*,*,#2073,.T.);
#2098=EDGE_LOOP('',(#2089,#2095,#2096,#2097));
#2099=FACE_BOUND('',#2098,.T.);
#2100=ADVANCED_FACE('F776',(#2099),#2088,.F.);
#2101=CARTESIAN_POINT('',(-20.,-5.,-17.5));
#2102=DIRECTION('',(0.,0.,-1.));
#2103=DIRECTION('',(-1.,0.,0.));
#2104=AXIS2_PLACEMENT_3D('',#2101,#2102,#2103);
#2105=PLANE('',#2104);
#2106=ORIENTED_EDGE('',*,*,#599,.F.);
#2107=ORIENTED_EDGE('',*,*,#627,.F.);
#2108=ORIENTED_EDGE('',*,*,#681,.F.);
#2109=ORIENTED_EDGE('',*,*,#707,.T.);
#2110=DIRECTION('',(0.,-1.,0.));
#2111=VECTOR('',#2110,1.);
#2112=CARTESIAN_POINT('',(-22.5,0.,-17.5));
#2113=LINE('',#2112,#2111);
#2114=EDGE_CURVE('E674',#1746,#704,#2113,.F.);
#2115=ORIENTED_EDGE('',*,*,#2114,.F.);
#2116=ORIENTED_EDGE('',*,*,#1747,.F.);
#2117=ORIENTED_EDGE('',*,*,#1721,.F.);
#2118=ORIENTED_EDGE('',*,*,#1695,.F.);
#2119=ORIENTED_EDGE('',*,*,#1669,.F.);
#2120=ORIENTED_EDGE('',*,*,#1643,.F.);
#2121=ORIENTED_EDGE('',*,*,#1617,.F.);
#2122=ORIENTED_EDGE('',*,*,#1591,.F.);
#2123=ORIENTED_EDGE('',*,*,#1565,.F.);
#2124=ORIENTED_EDGE('',*,*,#1539,.F.);
#2125=ORIENTED_EDGE('',*,*,#2094,.F.);
#2126=ORIENTED_EDGE('',*,*,#647,.T.);
#2127=EDGE_LOOP('',(#2106,#2107,#2108,#2109,#2115,#2116,#2117,#2118,#2119,#2120,#2121,#2122,
#2123,#2124,#2125,#2126));
#2128=FACE_BOUND('',#2127,.T.);
#2129=ADVANCED_FACE('F768',(#2128),#2105,.F.);
#2130=CARTESIAN_POINT('',(-22.5,0.,-15.));
#2131=DIRECTION('',(0.,1.,0.));
#2132=DIRECTION('',(0.,0.,1.));
#2133=AXIS2_PLACEMENT_3D('',#2130,#2131,#2132);
#2134=CYLINDRICAL_SURFACE('',#2133,2.5);
#2135=ORIENTED_EDGE('',*,*,#705,.T.);
#2136=DIRECTION('',(0.,-1.,0.));
#2137=VECTOR('',#2136,1.);
#2138=CARTESIAN_POINT('',(-25.,-5.,-15.));
#2139=LINE('',#2138,#2137);
#2140=EDGE_CURVE('E673',#695,#1755,#2139,.T.);
#2141=ORIENTED_EDGE('',*,*,#2140,.T.);
#2142=ORIENTED_EDGE('',*,*,#1756,.F.);
#2143=ORIENTED_EDGE('',*,*,#2114,.T.);
#2144=EDGE_LOOP('',(#2135,#2141,#2142,#2143));
#2145=FACE_BOUND('',#2144,.T.);
#2146=ADVANCED_FACE('F1379',(#2145),#2134,.F.);
#2147=CARTESIAN_POINT('',(-25.,0.,17.5));
#2148=DIRECTION('',(1.,0.,0.));
#2149=DIRECTION('',(0.,0.,-1.));
#2150=AXIS2_PLACEMENT_3D('',#2147,#2148,#2149);
#2151=PLANE('',#2150);
#2152=ORIENTED_EDGE('',*,*,#330,.F.);
#2153=ORIENTED_EDGE('',*,*,#353,.F.);
#2154=ORIENTED_EDGE('',*,*,#425,.F.);
#2155=DIRECTION('',(0.,-1.,0.));
#2156=VECTOR('',#2155,1.);
#2157=CARTESIAN_POINT('',(-25.,0.,15.));
#2158=LINE('',#2157,#2156);
#2159=EDGE_CURVE('E168',#1778,#418,#2158,.F.);
#2160=ORIENTED_EDGE('',*,*,#2159,.F.);
#2161=ORIENTED_EDGE('',*,*,#1779,.T.);
#2162=ORIENTED_EDGE('',*,*,#2140,.F.);
#2163=ORIENTED_EDGE('',*,*,#696,.F.);
#2164=ORIENTED_EDGE('',*,*,#301,.F.);
#2165=EDGE_LOOP('',(#2152,#2153,#2154,#2160,#2161,#2162,#2163,#2164));
#2166=FACE_BOUND('',#2165,.T.);
#2167=ADVANCED_FACE('F879',(#2166),#2151,.T.);
#2168=CARTESIAN_POINT('',(-22.5,-5.,15.));
#2169=DIRECTION('',(0.,-1.,0.));
#2170=DIRECTION('',(0.,0.,-1.));
#2171=AXIS2_PLACEMENT_3D('',#2168,#2169,#2170);
#2172=CYLINDRICAL_SURFACE('',#2171,2.5);
#2173=ORIENTED_EDGE('',*,*,#419,.T.);
#2174=DIRECTION('',(0.,-1.,0.));
#2175=VECTOR('',#2174,1.);
#2176=CARTESIAN_POINT('',(-22.5,-5.,17.5));
#2177=LINE('',#2176,#2175);
#2178=EDGE_CURVE('E13',#409,#1820,#2177,.T.);
#2179=ORIENTED_EDGE('',*,*,#2178,.T.);
#2180=ORIENTED_EDGE('',*,*,#1821,.F.);
#2181=ORIENTED_EDGE('',*,*,#2159,.T.);
#2182=EDGE_LOOP('',(#2173,#2179,#2180,#2181));
#2183=FACE_BOUND('',#2182,.T.);
#2184=ADVANCED_FACE('F1392',(#2183),#2172,.F.);
#2185=CARTESIAN_POINT('',(-20.,-5.,17.5));
#2186=DIRECTION('',(0.,0.,-1.));
#2187=DIRECTION('',(-1.,0.,0.));
#2188=AXIS2_PLACEMENT_3D('',#2185,#2186,#2187);
#2189=PLANE('',#2188);
#2190=ORIENTED_EDGE('',*,*,#574,.F.);
#2191=ORIENTED_EDGE('',*,*,#2058,.F.);
#2192=ORIENTED_EDGE('',*,*,#2036,.F.);
#2193=ORIENTED_EDGE('',*,*,#2010,.F.);
#2194=ORIENTED_EDGE('',*,*,#1984,.F.);
#2195=ORIENTED_EDGE('',*,*,#1958,.F.);
#2196=ORIENTED_EDGE('',*,*,#1932,.F.);
#2197=ORIENTED_EDGE('',*,*,#1906,.F.);
#2198=ORIENTED_EDGE('',*,*,#1880,.F.);
#2199=ORIENTED_EDGE('',*,*,#1854,.F.);
#2200=ORIENTED_EDGE('',*,*,#1828,.F.);
#2201=ORIENTED_EDGE('',*,*,#2178,.F.);
#2202=ORIENTED_EDGE('',*,*,#410,.F.);
#2203=ORIENTED_EDGE('',*,*,#466,.T.);
#2204=ORIENTED_EDGE('',*,*,#444,.T.);
#2205=ORIENTED_EDGE('',*,*,#379,.T.);
#2206=EDGE_LOOP('',(#2190,#2191,#2192,#2193,#2194,#2195,#2196,#2197,#2198,#2199,#2200,#2201,
#2202,#2203,#2204,#2205));
#2207=FACE_BOUND('',#2206,.T.);
#2208=ADVANCED_FACE('F1399',(#2207),#2189,.T.);
#2209=CLOSED_SHELL('',(#58,#121,#177,#233,#282,#312,#336,#359,#389,#431,#455,#472,#502,#526,
#549,#580,#609,#633,#664,#687,#714,#731,#751,#845,#862,#882,#976,#993,#1013,#1107,#1124,#1144,
#1238,#1280,#1313,#1346,#1379,#1412,#1445,#1478,#1517,#1551,#1577,#1603,#1629,#1655,#1681,#1707,
#1733,#1767,#1798,#1832,#1858,#1884,#1910,#1936,#1962,#1988,#2014,#2040,#2062,#2083,#2100,#2129,
#2146,#2167,#2184,#2208));
#2210=MANIFOLD_SOLID_BREP('B2',#2209);
#2211=ADVANCED_BREP_SHAPE_REPRESENTATION('',(#18,#2210),#14);
#2212=SHAPE_DEFINITION_REPRESENTATION(#9,#2211);
ENDSEC;
END-ISO-10303-21;
